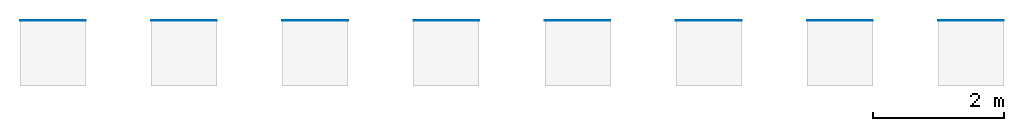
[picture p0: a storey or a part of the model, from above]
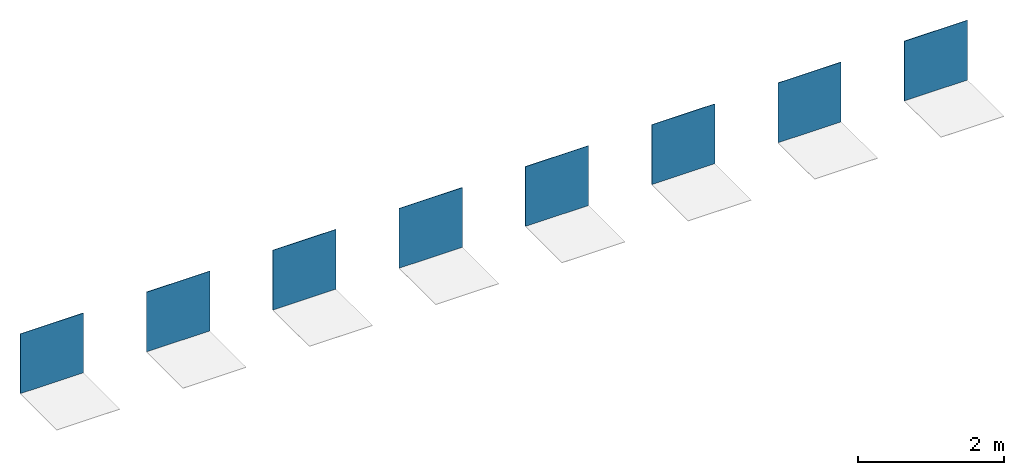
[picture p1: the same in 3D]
Properties of the parts of a building model (IFC2X3), part 1 of 2

# File
Description: ViewDefinition [CoordinationView_V2.0]
Time: 2025-06-20T12:25:39
Written by: The EXPRESS Data Manager Version 5.02.0100.07 : 28 Aug 2013
Made in: 21.1.90.15 - Exporter 21.1.90.15 - Alternate UI 21.1.90.15
Comment: STEP Physical File produced by: The EXPRESS Data Manager Version 5.02.0100.07 : 28 Aug 2013 * Module: EDMstepFileFactory/EDMstandAlone * Creation date: Fri Jun 20 12:25:39 2025 * Host: STB002 * Database: C:\Users\LARISS~1\AppData\Local\Temp\234e31d9-e186-458c-9206-d387dea7a233\4657faa5-0b9c-4604-aaa0-1ea8c5e9b940\ifc * Database version: 5507 * Database creation date: Fri Jun 20 12:25:38 2025 * Schema: IFC2X3 * Model: DataRepository.ifc * Model creation date: Fri Jun 20 12:25:39 2025 * Header model: DataRepository.ifc_HeaderModel * Header model creation date: Fri Jun 20 12:25:39 2025 * EDMuser: sdai-user * EDMgroup: sdai-group * License ID and type: 5605 : Permanent license. Expiry date: * EDMstepFileFactory options: 020000

# IfcSite, Default
RefLatitude: 42, 24, 53, 508911; RefLongitude: -71, -15, -29, -58837; RefElevation: 0 mm
Pset_ProductRequirements - Category: Project Information

# IfcBuilding
Pset_BuildingCommon - NumberOfStoreys: 1
Pset_ProductRequirements - Category: Project Information

# IfcBuildingStorey: Level:Level 1, Level 1
LongName: Level 1; Elevation: 0 mm
Pset_AirSideSystemInformation - Name: Level 1
Pset_ProductRequirements - Name: Level 1; Category: Levels

# IfcCovering: Floor:REVIGRÉS-LOCUS-HEXAGONO-16,5X19-SILK-ALLOY, Floor:REVIGRÉS-LOCUS-HEXAGONO-16,5X19-SILK-ALLOY:36414
In: Level 1
Type - PredefinedType: CLADDING; Material: REVIGRÉS-LOCUS-HEXAGONO-16,5x19-SILK-ALLOY 8.5 mm
Type - Pset_CoveringCommon - Reference: 332GV3V791; Material: Grés porcelânico
Type - Pset_ElementShading - Roughness: 304.8 mm
Type - Pset_ManufacturerTypeInformation - Manufacturer: REVIGRÉS
Type - Pset_ProductRequirements - Category: Floors
Type - Pset_QuantityTakeOff - Reference: 332GV3V791
Type - IFC.REVIGRÉS-Dados do fabricante-Floor Covering - FabricanteURL: https://www.revigres.pt/; ReferenciaModelo: Locus; NumeroGlobalDeItemComercial: 332GV3V761; Acabamento: SILK; Material: Grés porcelânico; IdentificadorDoOperadorEconomico: 501840856; UrlFabricanteArtigo: https://www.revigres.pt/colecoes/locus; PaisOrigem: Portugal
Type - IFC.REVIGRÉS-Dados de desempenho-Floor Covering - Rectilinearidade: ± 0.2% máx.± 0.8 mm; Ortogonalidade: ± 0.2% máx.± 1.5 mm; PlanaridadeDaSuperficie: ± 0.3% máx. ± 1.8 mm; QualidadeDaSuperficie: Cumpre; AbsorcaoDeAgua: < 0.05%; ModuloDeRuptura: > 45 N/mm²; ResistenciaAFlexao: > 2000 N; ResistenciaAAbrasaoProfunda: < 120 mm³; DilatacaoTermicaLinear: ≤ 8,0x10-6 °C-1; ResistenciaAoChoqueTermico: Resiste; DurabilidadeInterior: Cumpre; DurabilidadeResistenciaAoGeloDegelo: Resiste; ResistenciaAoEscorregamentoDIN51130: R9; ResistenciaAoEscorregamentoDIN51097: A; ResistenciaAoEscorregamentoENV51097: A; ResistenciaAoEscorregamentoENV12633: Class 1; ResistenciaAoEscorregamentoBS7976: -; ResistenciaAoEscorregamentoANSIA1371: ≥0,42; ResistenciaAoDeslizamentoENV12633: Class 1; ResistenciaAoDeslizamentoBS7976: -; ResistenciaAsManchas: Class 5; LibertacaoDeCadmio: 0; LibertacaoDeChumbo: 0
Type - IFC.REVIGRÉS-Dados de especificação-Floor Covering - VariacaoTonalidade: 3; NivelDeTrafego: 5; EPavimento: Sim; ERevestimento: Sim; EExterno: Sim
Type - IFC.REVIGRÉS-Dados geométricos-Floor Covering - AlturaNominal: 8.5 mm; ComprimentoNominal: 16.5 mm; LarguraNominal: 19 mm
Type - IFC.REVIGRÉS-Dados de sustentabilidade-Floor Covering - ItemEParcialmenteReciclado: 0; EnergiaTermicaExportada: 0; ItemENovo: Sim; ItemEReciclado: Não; VidaÚtilEsperada: 50; SubstanciasPerigosas: Não; PotencialDeEsgotamentoAbioticoDosRecursosNaoFosseisMineraisEMetais: 0.000701; PotencialDeAquecimentoGlobalBiogenico: -0.48; CombustiveisFosseisComPotencialDeAquecimentoGlobal: 13.9; PotencialDeAquecimentoGlobalUsoDoSoloEMudancaDeUsoDoSolo: 0.0246; PotencialDeEutrofizacaoFraccaoDeNutrientesQueAtingemOCompartimentoFinalDeAguaDoce: 0.000189; PotencialDeEutrofizacaoFraccaoDeNutrientesQueAtingemOCompartimentoFinalMarinho: 0.0122; EnergiaRecuperada: 0.00739; ConsumoDeAguaDoce: 0.113; UtilizacaoLiquidaDeAguaDoce: 0.113; ResiduosPerigososEliminados: 0.00221; ResiduosNaoPerigososEliminados: 1.83; MassaTotalDeResiduosRadioactivosEliminados: 0.000394; EnergiaElectricaExportada: 1.55; MateriaisParaRecuperacaoDeEnergia: 0.00739; MateriaisParaReciclagem: 0.0253; UnidadeEPD: 1 m²
Type - IFC.REVIGRÉS-Dados gerais-Floor Covering - Nome: REVIGRÉS-LOCUS-HEXAGONO-16.5x19-SILK-ALLOY; TipoProduto: Prensado a seco: grupo BIa UGL | Grés porcelânico técnico; NumeroDeRegistoDAP: EPD-REV-20240006-CCC1-EN; ReferenciaDAP: -; URL: https://www.revigres.pt/colecoes/locus
Classification: C3010 (Uniformat)
Pset_CoveringCommon - TotalThickness: 8.5 mm
IFC.REVIGRÉS-Dados do fabricante-Floor Covering - Type: Floor: REVIGRÉS-LOCUS-HEXAGONO-16,5X19-SILK-ALLOY
IFC.REVIGRÉS-Dados de desempenho-Floor Covering - Type: Floor: REVIGRÉS-LOCUS-HEXAGONO-16,5X19-SILK-ALLOY
IFC.REVIGRÉS-Dados de especificação-Floor Covering - Type: Floor: REVIGRÉS-LOCUS-HEXAGONO-16,5X19-SILK-ALLOY
IFC.REVIGRÉS-Dados geométricos-Floor Covering - Type: Floor: REVIGRÉS-LOCUS-HEXAGONO-16,5X19-SILK-ALLOY
IFC.REVIGRÉS-Dados de sustentabilidade-Floor Covering - Type: Floor: REVIGRÉS-LOCUS-HEXAGONO-16,5X19-SILK-ALLOY

# IfcCovering: Floor:REVIGRÉS-LOCUS-HEXAGONO-16,5X19-SILK-BONE, Floor:REVIGRÉS-LOCUS-HEXAGONO-16,5X19-SILK-BONE:36732
In: Level 1
Type - PredefinedType: CLADDING; Material: REVIGRÉS-LOCUS-HEXAGONO-16,5x19-SILK-BONE 8.5 mm
Type - Pset_CoveringCommon - Reference: 332GV3V781; Material: Grés porcelânico
Type - Pset_ElementShading - Roughness: 304.8 mm
Type - Pset_ManufacturerTypeInformation - Manufacturer: REVIGRÉS
Type - Pset_ProductRequirements - Category: Floors
Type - Pset_QuantityTakeOff - Reference: 332GV3V781
Type - IFC.REVIGRÉS-Dados do fabricante-Floor Covering - FabricanteURL: https://www.revigres.pt/; ReferenciaModelo: Locus; NumeroGlobalDeItemComercial: 312GV3V771; Acabamento: SILK; Material: Grés porcelânico; IdentificadorDoOperadorEconomico: 501840856; UrlFabricanteArtigo: https://www.revigres.pt/colecoes/locus; PaisOrigem: Portugal
Type - IFC.REVIGRÉS-Dados de desempenho-Floor Covering - Rectilinearidade: ± 0.2% máx.± 0.8 mm; Ortogonalidade: ± 0.2% máx.± 1.5 mm; PlanaridadeDaSuperficie: ± 0.3% máx. ± 1.8 mm; QualidadeDaSuperficie: Cumpre; AbsorcaoDeAgua: < 0.05%; ModuloDeRuptura: > 45 N/mm²; ResistenciaAFlexao: > 2000 N; ResistenciaAAbrasaoProfunda: < 120 mm³; DilatacaoTermicaLinear: ≤ 8,0x10-6 °C-1; ResistenciaAoChoqueTermico: Resiste; DurabilidadeInterior: Cumpre; DurabilidadeResistenciaAoGeloDegelo: Resiste; ResistenciaAoEscorregamentoDIN51130: R9; ResistenciaAoEscorregamentoDIN51097: A; ResistenciaAoEscorregamentoENV51097: A; ResistenciaAoEscorregamentoENV12633: Class 1; ResistenciaAoEscorregamentoBS7976: -; ResistenciaAoEscorregamentoANSIA1371: ≥0,42; ResistenciaAoDeslizamentoENV12633: Class 1; ResistenciaAoDeslizamentoBS7976: -; ResistenciaAsManchas: Class 5; LibertacaoDeCadmio: 0; LibertacaoDeChumbo: 0
Type - IFC.REVIGRÉS-Dados de especificação-Floor Covering - VariacaoTonalidade: 3; NivelDeTrafego: 5; EPavimento: Sim; ERevestimento: Sim; EExterno: Sim
Type - IFC.REVIGRÉS-Dados geométricos-Floor Covering - AlturaNominal: 8.5 mm; ComprimentoNominal: 16.5 mm; LarguraNominal: 19 mm
Type - IFC.REVIGRÉS-Dados de sustentabilidade-Floor Covering - ItemEParcialmenteReciclado: 0; EnergiaTermicaExportada: 0; ItemENovo: Sim; ItemEReciclado: Não; VidaÚtilEsperada: 50; SubstanciasPerigosas: Não; PotencialDeEsgotamentoAbioticoDosRecursosNaoFosseisMineraisEMetais: 0.000701; PotencialDeAquecimentoGlobalBiogenico: -0.48; CombustiveisFosseisComPotencialDeAquecimentoGlobal: 13.9; PotencialDeAquecimentoGlobalUsoDoSoloEMudancaDeUsoDoSolo: 0.0246; PotencialDeEutrofizacaoFraccaoDeNutrientesQueAtingemOCompartimentoFinalDeAguaDoce: 0.000189; PotencialDeEutrofizacaoFraccaoDeNutrientesQueAtingemOCompartimentoFinalMarinho: 0.0122; EnergiaRecuperada: 0.00739; ConsumoDeAguaDoce: 0.113; UtilizacaoLiquidaDeAguaDoce: 0.113; ResiduosPerigososEliminados: 0.00221; ResiduosNaoPerigososEliminados: 1.83; MassaTotalDeResiduosRadioactivosEliminados: 0.000394; EnergiaElectricaExportada: 1.55; MateriaisParaRecuperacaoDeEnergia: 0.00739; MateriaisParaReciclagem: 0.0253; UnidadeEPD: 1 m²
Type - IFC.REVIGRÉS-Dados gerais-Floor Covering - Nome: REVIGRÉS-LOCUS-HEXAGONO-16.5x19-SILK-BONE; TipoProduto: Prensado a seco: grupo BIa UGL | Grés porcelânico técnico; NumeroDeRegistoDAP: EPD-REV-20240006-CCC1-EN; ReferenciaDAP: -; URL: https://www.revigres.pt/colecoes/locus
Classification: C3010 (Uniformat)
Pset_CoveringCommon - TotalThickness: 8.5 mm
IFC.REVIGRÉS-Dados do fabricante-Floor Covering - Type: Floor: REVIGRÉS-LOCUS-HEXAGONO-16,5X19-SILK-BONE
IFC.REVIGRÉS-Dados de desempenho-Floor Covering - Type: Floor: REVIGRÉS-LOCUS-HEXAGONO-16,5X19-SILK-BONE
IFC.REVIGRÉS-Dados de especificação-Floor Covering - Type: Floor: REVIGRÉS-LOCUS-HEXAGONO-16,5X19-SILK-BONE
IFC.REVIGRÉS-Dados geométricos-Floor Covering - Type: Floor: REVIGRÉS-LOCUS-HEXAGONO-16,5X19-SILK-BONE
IFC.REVIGRÉS-Dados de sustentabilidade-Floor Covering - Type: Floor: REVIGRÉS-LOCUS-HEXAGONO-16,5X19-SILK-BONE

# IfcCovering: Floor:REVIGRÉS-LOCUS-HEXAGONO-16,5X19-SILK-GRIS, Floor:REVIGRÉS-LOCUS-HEXAGONO-16,5X19-SILK-GRIS:37396
In: Level 1
Type - PredefinedType: CLADDING; Material: REVIGRÉS-LOCUS-HEXAGONO-16,5x19-SILK-GRIS 8.5 mm
Type - Pset_CoveringCommon - Reference: 312GV3V771; Material: Grés porcelânico
Type - Pset_ElementShading - Roughness: 304.8 mm
Type - Pset_ManufacturerTypeInformation - Manufacturer: REVIGRÉS
Type - Pset_ProductRequirements - Category: Floors
Type - Pset_QuantityTakeOff - Reference: 312GV3V771
Type - IFC.REVIGRÉS-Dados do fabricante-Floor Covering - FabricanteURL: https://www.revigres.pt/; ReferenciaModelo: Locus; NumeroGlobalDeItemComercial: 332GV3V781; Acabamento: SILK; Material: Grés porcelânico; IdentificadorDoOperadorEconomico: 501840856; UrlFabricanteArtigo: https://www.revigres.pt/colecoes/locus; PaisOrigem: Portugal
Type - IFC.REVIGRÉS-Dados de desempenho-Floor Covering - Rectilinearidade: ± 0.2% máx.± 0.8 mm; Ortogonalidade: ± 0.2% máx.± 1.5 mm; PlanaridadeDaSuperficie: ± 0.3% máx. ± 1.8 mm; QualidadeDaSuperficie: Cumpre; AbsorcaoDeAgua: < 0.05%; ModuloDeRuptura: > 45 N/mm²; ResistenciaAFlexao: > 2000 N; ResistenciaAAbrasaoProfunda: < 120 mm³; DilatacaoTermicaLinear: ≤ 8,0x10-6 °C-1; ResistenciaAoChoqueTermico: Resiste; DurabilidadeInterior: Cumpre; DurabilidadeResistenciaAoGeloDegelo: Resiste; ResistenciaAoEscorregamentoDIN51130: R9; ResistenciaAoEscorregamentoDIN51097: A; ResistenciaAoEscorregamentoENV51097: A; ResistenciaAoEscorregamentoENV12633: Class 1; ResistenciaAoEscorregamentoBS7976: -; ResistenciaAoEscorregamentoANSIA1371: ≥0,42; ResistenciaAoDeslizamentoENV12633: Class 1; ResistenciaAoDeslizamentoBS7976: -; ResistenciaAsManchas: Class 5; LibertacaoDeCadmio: 0; LibertacaoDeChumbo: 0
Type - IFC.REVIGRÉS-Dados de especificação-Floor Covering - VariacaoTonalidade: 3; NivelDeTrafego: 5; EPavimento: Sim; ERevestimento: Sim; EExterno: Sim
Type - IFC.REVIGRÉS-Dados geométricos-Floor Covering - AlturaNominal: 8.5 mm; ComprimentoNominal: 16.5 mm; LarguraNominal: 19 mm
Type - IFC.REVIGRÉS-Dados de sustentabilidade-Floor Covering - EnergiaTermicaExportada: 0; ItemENovo: Sim; ItemEParcialmenteReciclado: 0.23; ItemEReciclado: Sim; VidaÚtilEsperada: 50; SubstanciasPerigosas: Não; PotencialDeEsgotamentoAbioticoDosRecursosNaoFosseisMineraisEMetais: 0.000701; PotencialDeAquecimentoGlobalBiogenico: -0.48; CombustiveisFosseisComPotencialDeAquecimentoGlobal: 13.9; PotencialDeAquecimentoGlobalUsoDoSoloEMudancaDeUsoDoSolo: 0.0246; PotencialDeEutrofizacaoFraccaoDeNutrientesQueAtingemOCompartimentoFinalDeAguaDoce: 0.000189; PotencialDeEutrofizacaoFraccaoDeNutrientesQueAtingemOCompartimentoFinalMarinho: 0.0122; EnergiaRecuperada: 0.00739; ConsumoDeAguaDoce: 0.113; UtilizacaoLiquidaDeAguaDoce: 0.113; ResiduosPerigososEliminados: 0.00221; ResiduosNaoPerigososEliminados: 1.83; MassaTotalDeResiduosRadioactivosEliminados: 0.000394; EnergiaElectricaExportada: 1.55; MateriaisParaRecuperacaoDeEnergia: 0.00739; MateriaisParaReciclagem: 0.0253; UnidadeEPD: 1 m²
Type - IFC.REVIGRÉS-Dados gerais-Floor Covering - Nome: REVIGRÉS-LOCUS-HEXAGONO-16.5x19-SILK-GRIS; TipoProduto: Prensado a seco: grupo BIa UGL | Grés porcelânico técnico; NumeroDeRegistoDAP: EPD-REV-20240006-CCC1-EN; ReferenciaDAP: -; URL: https://www.revigres.pt/colecoes/locus
Classification: C3010 (Uniformat)
Pset_CoveringCommon - TotalThickness: 8.5 mm
IFC.REVIGRÉS-Dados do fabricante-Floor Covering - Type: Floor: REVIGRÉS-LOCUS-HEXAGONO-16,5X19-SILK-GRIS
IFC.REVIGRÉS-Dados de desempenho-Floor Covering - Type: Floor: REVIGRÉS-LOCUS-HEXAGONO-16,5X19-SILK-GRIS
IFC.REVIGRÉS-Dados de especificação-Floor Covering - Type: Floor: REVIGRÉS-LOCUS-HEXAGONO-16,5X19-SILK-GRIS
IFC.REVIGRÉS-Dados geométricos-Floor Covering - Type: Floor: REVIGRÉS-LOCUS-HEXAGONO-16,5X19-SILK-GRIS
IFC.REVIGRÉS-Dados de sustentabilidade-Floor Covering - Type: Floor: REVIGRÉS-LOCUS-HEXAGONO-16,5X19-SILK-GRIS

# IfcCovering: Floor:REVIGRÉS-LOCUS-HEXAGONO-16,5X19-SILK-SMOG, Floor:REVIGRÉS-LOCUS-HEXAGONO-16,5X19-SILK-SMOG:37911
In: Level 1
Type - PredefinedType: CLADDING; Material: REVIGRÉS-LOCUS-HEXAGONO-16,5x19-SILK-SMOG 8.5 mm
Type - Pset_CoveringCommon - Reference: 332GV3V761; Material: Grés porcelânico
Type - Pset_ElementShading - Roughness: 304.8 mm
Type - Pset_ManufacturerTypeInformation - Manufacturer: REVIGRÉS
Type - Pset_ProductRequirements - Category: Floors
Type - Pset_QuantityTakeOff - Reference: 332GV3V761
Type - IFC.REVIGRÉS-Dados do fabricante-Floor Covering - FabricanteURL: https://www.revigres.pt/; ReferenciaModelo: Locus; NumeroGlobalDeItemComercial: 332GV3V791; Acabamento: SILK; Material: Grés porcelânico; IdentificadorDoOperadorEconomico: 501840856; UrlFabricanteArtigo: https://www.revigres.pt/colecoes/locus; PaisOrigem: Portugal
Type - IFC.REVIGRÉS-Dados de desempenho-Floor Covering - Rectilinearidade: ± 0.2% máx.± 0.8 mm; Ortogonalidade: ± 0.2% máx.± 1.5 mm; PlanaridadeDaSuperficie: ± 0.3% máx. ± 1.8 mm; QualidadeDaSuperficie: Cumpre; AbsorcaoDeAgua: < 0.05%; ModuloDeRuptura: > 45 N/mm²; ResistenciaAFlexao: > 2000 N; ResistenciaAAbrasaoProfunda: < 120 mm³; DilatacaoTermicaLinear: ≤ 8,0x10-6 °C-1; ResistenciaAoChoqueTermico: Resiste; DurabilidadeInterior: Cumpre; DurabilidadeResistenciaAoGeloDegelo: Resiste; ResistenciaAoEscorregamentoDIN51130: R9; ResistenciaAoEscorregamentoDIN51097: A; ResistenciaAoEscorregamentoENV51097: A; ResistenciaAoEscorregamentoENV12633: Class 1; ResistenciaAoEscorregamentoBS7976: -; ResistenciaAoEscorregamentoANSIA1371: ≥0,42; ResistenciaAoDeslizamentoENV12633: Class 1; ResistenciaAoDeslizamentoBS7976: -; ResistenciaAsManchas: Class 5; LibertacaoDeCadmio: 0; LibertacaoDeChumbo: 0
Type - IFC.REVIGRÉS-Dados de especificação-Floor Covering - VariacaoTonalidade: 3; NivelDeTrafego: 5; EPavimento: Sim; ERevestimento: Sim; EExterno: Sim
Type - IFC.REVIGRÉS-Dados geométricos-Floor Covering - AlturaNominal: 8.5 mm; ComprimentoNominal: 16.5 mm; LarguraNominal: 19 mm
Type - IFC.REVIGRÉS-Dados de sustentabilidade-Floor Covering - EnergiaTermicaExportada: 0; ItemENovo: Sim; ItemEParcialmenteReciclado: 0.29; ItemEReciclado: Sim; VidaÚtilEsperada: 50; SubstanciasPerigosas: Não; PotencialDeEsgotamentoAbioticoDosRecursosNaoFosseisMineraisEMetais: 0.000701; PotencialDeAquecimentoGlobalBiogenico: -0.48; CombustiveisFosseisComPotencialDeAquecimentoGlobal: 13.9; PotencialDeAquecimentoGlobalUsoDoSoloEMudancaDeUsoDoSolo: 0.0246; PotencialDeEutrofizacaoFraccaoDeNutrientesQueAtingemOCompartimentoFinalDeAguaDoce: 0.000189; PotencialDeEutrofizacaoFraccaoDeNutrientesQueAtingemOCompartimentoFinalMarinho: 0.0122; EnergiaRecuperada: 0.00739; ConsumoDeAguaDoce: 0.113; UtilizacaoLiquidaDeAguaDoce: 0.113; ResiduosPerigososEliminados: 0.00221; ResiduosNaoPerigososEliminados: 1.83; MassaTotalDeResiduosRadioactivosEliminados: 0.000394; EnergiaElectricaExportada: 1.55; MateriaisParaRecuperacaoDeEnergia: 0.00739; MateriaisParaReciclagem: 0.0253; UnidadeEPD: 1 m²
Type - IFC.REVIGRÉS-Dados gerais-Floor Covering - Nome: REVIGRÉS-LOCUS-HEXAGONO-16.5x19-SILK-SMOG; TipoProduto: Prensado a seco: grupo BIa UGL | Grés porcelânico técnico; NumeroDeRegistoDAP: EPD-REV-20240006-CCC1-EN; ReferenciaDAP: -; URL: https://www.revigres.pt/colecoes/locus
Classification: C3010 (Uniformat)
Pset_CoveringCommon - TotalThickness: 8.5 mm
IFC.REVIGRÉS-Dados do fabricante-Floor Covering - Type: Floor: REVIGRÉS-LOCUS-HEXAGONO-16,5X19-SILK-SMOG
IFC.REVIGRÉS-Dados de desempenho-Floor Covering - Type: Floor: REVIGRÉS-LOCUS-HEXAGONO-16,5X19-SILK-SMOG
IFC.REVIGRÉS-Dados de especificação-Floor Covering - Type: Floor: REVIGRÉS-LOCUS-HEXAGONO-16,5X19-SILK-SMOG
IFC.REVIGRÉS-Dados geométricos-Floor Covering - Type: Floor: REVIGRÉS-LOCUS-HEXAGONO-16,5X19-SILK-SMOG
IFC.REVIGRÉS-Dados de sustentabilidade-Floor Covering - Type: Floor: REVIGRÉS-LOCUS-HEXAGONO-16,5X19-SILK-SMOG

# IfcCovering: Floor:REVIGRÉS-LOCUS-HEXAGONO-16,5X19-SOFT GRIP-ALLOY, Floor:REVIGRÉS-LOCUS-HEXAGONO-16,5X19-SOFT GRIP-ALLOY:112818
In: Level 1
Type - PredefinedType: CLADDING; Material: REVIGRÉS-LOCUS-HEXAGONO-16,5x19-SILK-ALLOY 8.5 mm
Type - Pset_CoveringCommon - Reference: 332FV3V761; Material: Grés porcelânico
Type - Pset_ElementShading - Roughness: 304.8 mm
Type - Pset_ManufacturerTypeInformation - Manufacturer: REVIGRÉS
Type - Pset_ProductRequirements - Category: Floors
Type - Pset_QuantityTakeOff - Reference: 332FV3V761
Type - IFC.REVIGRÉS-Dados do fabricante-Floor Covering - FabricanteURL: https://www.revigres.pt/; ReferenciaModelo: Locus; NumeroGlobalDeItemComercial: 332FV3V761; Acabamento: SOFT; Material: Grés porcelânico; IdentificadorDoOperadorEconomico: 501840856; UrlFabricanteArtigo: https://www.revigres.pt/colecoes/locus; PaisOrigem: Portugal
Type - IFC.REVIGRÉS-Dados de desempenho-Floor Covering - Rectilinearidade: ± 0.2% máx ± 1.0 mm; Ortogonalidade: ± 0.2% máx.± 1.5 mm; PlanaridadeDaSuperficie: ± 0.3% máx. ± 1.8 mm; QualidadeDaSuperficie: Cumpre; AbsorcaoDeAgua: < 0.05%; ModuloDeRuptura: > 45 N/mm²; ResistenciaAFlexao: > 2000 N; ResistenciaAAbrasaoProfunda: < 120 mm³; DilatacaoTermicaLinear: ≤ 8,0x10-6 °C-1; ResistenciaAoChoqueTermico: Resiste; DurabilidadeInterior: Cumpre; DurabilidadeResistenciaAoGeloDegelo: Resiste; ResistenciaAoEscorregamentoDIN51130: R11; ResistenciaAoEscorregamentoDIN51097: A; ResistenciaAoEscorregamentoENV51097: A; ResistenciaAoEscorregamentoENV12633: Class 2; ResistenciaAoEscorregamentoBS7976: > 36; ResistenciaAoEscorregamentoANSIA1371: ≥0,42; ResistenciaAoDeslizamentoENV12633: Class 2; ResistenciaAoDeslizamentoBS7976: > 36; ResistenciaAsManchas: Class 5; LibertacaoDeCadmio: 0; LibertacaoDeChumbo: 0
Type - IFC.REVIGRÉS-Dados de especificação-Floor Covering - VariacaoTonalidade: 3; NivelDeTrafego: 5; EPavimento: Sim; ERevestimento: Sim; EExterno: Sim
Type - IFC.REVIGRÉS-Dados geométricos-Floor Covering - AlturaNominal: 8.5 mm; ComprimentoNominal: 16.5 mm; LarguraNominal: 19 mm
Type - IFC.REVIGRÉS-Dados de sustentabilidade-Floor Covering - ItemEParcialmenteReciclado: 0; EnergiaTermicaExportada: 0; ItemENovo: Sim; ItemEReciclado: Não; VidaÚtilEsperada: 50; SubstanciasPerigosas: Não; PotencialDeEsgotamentoAbioticoDosRecursosNaoFosseisMineraisEMetais: 0.000701; PotencialDeAquecimentoGlobalBiogenico: -0.48; CombustiveisFosseisComPotencialDeAquecimentoGlobal: 13.9; PotencialDeAquecimentoGlobalUsoDoSoloEMudancaDeUsoDoSolo: 0.0246; PotencialDeEutrofizacaoFraccaoDeNutrientesQueAtingemOCompartimentoFinalDeAguaDoce: 0.000189; PotencialDeEutrofizacaoFraccaoDeNutrientesQueAtingemOCompartimentoFinalMarinho: 0.0122; EnergiaRecuperada: 0.00739; ConsumoDeAguaDoce: 0.113; UtilizacaoLiquidaDeAguaDoce: 0.113; ResiduosPerigososEliminados: 0.00221; ResiduosNaoPerigososEliminados: 1.83; MassaTotalDeResiduosRadioactivosEliminados: 0.000394; EnergiaElectricaExportada: 1.55; MateriaisParaRecuperacaoDeEnergia: 0.00739; MateriaisParaReciclagem: 0.0253; UnidadeEPD: 1 m²
Type - IFC.REVIGRÉS-Dados gerais-Floor Covering - Nome: REVIGRÉS-LOCUS-HEXAGONO-16.5x19-SOFT GRIP-ALLOY; TipoProduto: Prensado a seco: grupo BIa UGL | Grés porcelânico técnico; NumeroDeRegistoDAP: EPD-REV-20240006-CCC1-EN; ReferenciaDAP: -; URL: https://www.revigres.pt/colecoes/locus
Classification: C3010 (Uniformat)
Pset_CoveringCommon - TotalThickness: 8.5 mm
IFC.REVIGRÉS-Dados do fabricante-Floor Covering - Type: Floor: REVIGRÉS-LOCUS-HEXAGONO-16,5X19-SOFT GRIP-ALLOY
IFC.REVIGRÉS-Dados de desempenho-Floor Covering - Type: Floor: REVIGRÉS-LOCUS-HEXAGONO-16,5X19-SOFT GRIP-ALLOY
IFC.REVIGRÉS-Dados de especificação-Floor Covering - Type: Floor: REVIGRÉS-LOCUS-HEXAGONO-16,5X19-SOFT GRIP-ALLOY
IFC.REVIGRÉS-Dados geométricos-Floor Covering - Type: Floor: REVIGRÉS-LOCUS-HEXAGONO-16,5X19-SOFT GRIP-ALLOY
IFC.REVIGRÉS-Dados de sustentabilidade-Floor Covering - Type: Floor: REVIGRÉS-LOCUS-HEXAGONO-16,5X19-SOFT GRIP-ALLOY

# IfcCovering: Floor:REVIGRÉS-LOCUS-HEXAGONO-16,5X19-SOFT GRIP-BONE, Floor:REVIGRÉS-LOCUS-HEXAGONO-16,5X19-SOFT GRIP-BONE:112826
In: Level 1
Type - PredefinedType: CLADDING; Material: REVIGRÉS-LOCUS-HEXAGONO-16,5x19-SILK-BONE 8.5 mm
Type - Pset_CoveringCommon - Reference: 332FV3V771; Material: Grés porcelânico
Type - Pset_ElementShading - Roughness: 304.8 mm
Type - Pset_ManufacturerTypeInformation - Manufacturer: REVIGRÉS
Type - Pset_ProductRequirements - Category: Floors
Type - Pset_QuantityTakeOff - Reference: 332FV3V771
Type - IFC.REVIGRÉS-Dados do fabricante-Floor Covering - FabricanteURL: https://www.revigres.pt/; ReferenciaModelo: Locus; NumeroGlobalDeItemComercial: 332FV3V771; Acabamento: SOFT; Material: Grés porcelânico; IdentificadorDoOperadorEconomico: 501840856; UrlFabricanteArtigo: https://www.revigres.pt/colecoes/locus; PaisOrigem: Portugal
Type - IFC.REVIGRÉS-Dados de desempenho-Floor Covering - Rectilinearidade: ± 0.2% máx ± 1.0 mm; Ortogonalidade: ± 0.2% máx.± 1.5 mm; PlanaridadeDaSuperficie: ± 0.3% máx. ± 1.8 mm; QualidadeDaSuperficie: Cumpre; AbsorcaoDeAgua: < 0.05%; ModuloDeRuptura: > 45 N/mm²; ResistenciaAFlexao: > 2000 N; ResistenciaAAbrasaoProfunda: < 120 mm³; DilatacaoTermicaLinear: ≤ 8,0x10-6 °C-1; ResistenciaAoChoqueTermico: Resiste; DurabilidadeInterior: Cumpre; DurabilidadeResistenciaAoGeloDegelo: Resiste; ResistenciaAoEscorregamentoDIN51130: R11; ResistenciaAoEscorregamentoDIN51097: A; ResistenciaAoEscorregamentoENV51097: A; ResistenciaAoEscorregamentoENV12633: Class 2; ResistenciaAoEscorregamentoBS7976: > 36; ResistenciaAoEscorregamentoANSIA1371: ≥0,42; ResistenciaAoDeslizamentoENV12633: Class 2; ResistenciaAoDeslizamentoBS7976: > 36; ResistenciaAsManchas: Class 5; LibertacaoDeCadmio: 0; LibertacaoDeChumbo: 0
Type - IFC.REVIGRÉS-Dados de especificação-Floor Covering - VariacaoTonalidade: 3; NivelDeTrafego: 5; EPavimento: Sim; ERevestimento: Sim; EExterno: Sim
Type - IFC.REVIGRÉS-Dados geométricos-Floor Covering - AlturaNominal: 8.5 mm; ComprimentoNominal: 16.5 mm; LarguraNominal: 19 mm
Type - IFC.REVIGRÉS-Dados de sustentabilidade-Floor Covering - ItemEParcialmenteReciclado: 0; EnergiaTermicaExportada: 0; ItemENovo: Sim; ItemEReciclado: Não; VidaÚtilEsperada: 50; SubstanciasPerigosas: Não; PotencialDeEsgotamentoAbioticoDosRecursosNaoFosseisMineraisEMetais: 0.000701; PotencialDeAquecimentoGlobalBiogenico: -0.48; CombustiveisFosseisComPotencialDeAquecimentoGlobal: 13.9; PotencialDeAquecimentoGlobalUsoDoSoloEMudancaDeUsoDoSolo: 0.0246; PotencialDeEutrofizacaoFraccaoDeNutrientesQueAtingemOCompartimentoFinalDeAguaDoce: 0.000189; PotencialDeEutrofizacaoFraccaoDeNutrientesQueAtingemOCompartimentoFinalMarinho: 0.0122; EnergiaRecuperada: 0.00739; ConsumoDeAguaDoce: 0.113; UtilizacaoLiquidaDeAguaDoce: 0.113; ResiduosPerigososEliminados: 0.00221; ResiduosNaoPerigososEliminados: 1.83; MassaTotalDeResiduosRadioactivosEliminados: 0.000394; EnergiaElectricaExportada: 1.55; MateriaisParaRecuperacaoDeEnergia: 0.00739; MateriaisParaReciclagem: 0.0253; UnidadeEPD: 1 m²
Type - IFC.REVIGRÉS-Dados gerais-Floor Covering - Nome: REVIGRÉS-LOCUS-HEXAGONO-16.5x19-SOFT GRIP-BONE; TipoProduto: Prensado a seco: grupo BIa UGL | Grés porcelânico técnico; NumeroDeRegistoDAP: EPD-REV-20240006-CCC1-EN; ReferenciaDAP: -; URL: https://www.revigres.pt/colecoes/locus
Classification: C3010 (Uniformat)
Pset_CoveringCommon - TotalThickness: 8.5 mm
IFC.REVIGRÉS-Dados do fabricante-Floor Covering - Type: Floor: REVIGRÉS-LOCUS-HEXAGONO-16,5X19-SOFT GRIP-BONE
IFC.REVIGRÉS-Dados de desempenho-Floor Covering - Type: Floor: REVIGRÉS-LOCUS-HEXAGONO-16,5X19-SOFT GRIP-BONE
IFC.REVIGRÉS-Dados de especificação-Floor Covering - Type: Floor: REVIGRÉS-LOCUS-HEXAGONO-16,5X19-SOFT GRIP-BONE
IFC.REVIGRÉS-Dados geométricos-Floor Covering - Type: Floor: REVIGRÉS-LOCUS-HEXAGONO-16,5X19-SOFT GRIP-BONE
IFC.REVIGRÉS-Dados de sustentabilidade-Floor Covering - Type: Floor: REVIGRÉS-LOCUS-HEXAGONO-16,5X19-SOFT GRIP-BONE

# IfcCovering: Floor:REVIGRÉS-LOCUS-HEXAGONO-16,5X19-SOFT GRIP-GRIS, Floor:REVIGRÉS-LOCUS-HEXAGONO-16,5X19-SOFT GRIP-GRIS:112834
In: Level 1
Type - PredefinedType: CLADDING; Material: REVIGRÉS-LOCUS-HEXAGONO-16,5x19-SILK-GRIS 8.5 mm
Type - Pset_CoveringCommon - Reference: 332FV3V781; Material: Grés porcelânico
Type - Pset_ElementShading - Roughness: 304.8 mm
Type - Pset_ManufacturerTypeInformation - Manufacturer: REVIGRÉS
Type - Pset_ProductRequirements - Category: Floors
Type - Pset_QuantityTakeOff - Reference: 332FV3V781
Type - IFC.REVIGRÉS-Dados do fabricante-Floor Covering - FabricanteURL: https://www.revigres.pt/; ReferenciaModelo: Locus; NumeroGlobalDeItemComercial: 332FV3V781; Acabamento: SOFT; Material: Grés porcelânico; IdentificadorDoOperadorEconomico: 501840856; UrlFabricanteArtigo: https://www.revigres.pt/colecoes/locus; PaisOrigem: Portugal
Type - IFC.REVIGRÉS-Dados de desempenho-Floor Covering - Rectilinearidade: ± 0.2% máx ± 1.0 mm; Ortogonalidade: ± 0.2% máx.± 1.5 mm; PlanaridadeDaSuperficie: ± 0.3% máx. ± 1.8 mm; QualidadeDaSuperficie: Cumpre; AbsorcaoDeAgua: < 0.05%; ModuloDeRuptura: > 45 N/mm²; ResistenciaAFlexao: > 2000 N; ResistenciaAAbrasaoProfunda: < 120 mm³; DilatacaoTermicaLinear: ≤ 8,0x10-6 °C-1; ResistenciaAoChoqueTermico: Resiste; DurabilidadeInterior: Cumpre; DurabilidadeResistenciaAoGeloDegelo: Resiste; ResistenciaAoEscorregamentoDIN51130: R11; ResistenciaAoEscorregamentoDIN51097: A; ResistenciaAoEscorregamentoENV51097: A; ResistenciaAoEscorregamentoENV12633: Class 2; ResistenciaAoEscorregamentoBS7976: > 36; ResistenciaAoEscorregamentoANSIA1371: ≥0,42; ResistenciaAoDeslizamentoENV12633: Class 2; ResistenciaAoDeslizamentoBS7976: > 36; ResistenciaAsManchas: Class 5; LibertacaoDeCadmio: 0; LibertacaoDeChumbo: 0
Type - IFC.REVIGRÉS-Dados de especificação-Floor Covering - VariacaoTonalidade: 3; NivelDeTrafego: 5; EPavimento: Sim; ERevestimento: Sim; EExterno: Sim
Type - IFC.REVIGRÉS-Dados geométricos-Floor Covering - AlturaNominal: 8.5 mm; ComprimentoNominal: 16.5 mm; LarguraNominal: 19 mm
Type - IFC.REVIGRÉS-Dados de sustentabilidade-Floor Covering - EnergiaTermicaExportada: 0; ItemENovo: Sim; ItemEParcialmenteReciclado: 0.23; ItemEReciclado: Sim; VidaÚtilEsperada: 50; SubstanciasPerigosas: Não; PotencialDeEsgotamentoAbioticoDosRecursosNaoFosseisMineraisEMetais: 0.000701; PotencialDeAquecimentoGlobalBiogenico: -0.48; CombustiveisFosseisComPotencialDeAquecimentoGlobal: 13.9; PotencialDeAquecimentoGlobalUsoDoSoloEMudancaDeUsoDoSolo: 0.0246; PotencialDeEutrofizacaoFraccaoDeNutrientesQueAtingemOCompartimentoFinalDeAguaDoce: 0.000189; PotencialDeEutrofizacaoFraccaoDeNutrientesQueAtingemOCompartimentoFinalMarinho: 0.0122; EnergiaRecuperada: 0.00739; ConsumoDeAguaDoce: 0.113; UtilizacaoLiquidaDeAguaDoce: 0.113; ResiduosPerigososEliminados: 0.00221; ResiduosNaoPerigososEliminados: 1.83; MassaTotalDeResiduosRadioactivosEliminados: 0.000394; EnergiaElectricaExportada: 1.55; MateriaisParaRecuperacaoDeEnergia: 0.00739; MateriaisParaReciclagem: 0.0253; UnidadeEPD: 1 m²
Type - IFC.REVIGRÉS-Dados gerais-Floor Covering - Nome: REVIGRÉS-LOCUS-HEXAGONO-16.5x19-SOFT GRIP-GRIS; TipoProduto: Prensado a seco: grupo BIa UGL | Grés porcelânico técnico; NumeroDeRegistoDAP: EPD-REV-20240006-CCC1-EN; ReferenciaDAP: -; URL: https://www.revigres.pt/colecoes/locus
Classification: C3010 (Uniformat)
Pset_CoveringCommon - TotalThickness: 8.5 mm
IFC.REVIGRÉS-Dados do fabricante-Floor Covering - Type: Floor: REVIGRÉS-LOCUS-HEXAGONO-16,5X19-SOFT GRIP-GRIS
IFC.REVIGRÉS-Dados de desempenho-Floor Covering - Type: Floor: REVIGRÉS-LOCUS-HEXAGONO-16,5X19-SOFT GRIP-GRIS
IFC.REVIGRÉS-Dados de especificação-Floor Covering - Type: Floor: REVIGRÉS-LOCUS-HEXAGONO-16,5X19-SOFT GRIP-GRIS
IFC.REVIGRÉS-Dados geométricos-Floor Covering - Type: Floor: REVIGRÉS-LOCUS-HEXAGONO-16,5X19-SOFT GRIP-GRIS
IFC.REVIGRÉS-Dados de sustentabilidade-Floor Covering - Type: Floor: REVIGRÉS-LOCUS-HEXAGONO-16,5X19-SOFT GRIP-GRIS

# IfcCovering: Floor:REVIGRÉS-LOCUS-HEXAGONO-16,5X19-SOFT GRIP-SMOG, Floor:REVIGRÉS-LOCUS-HEXAGONO-16,5X19-SOFT GRIP-SMOG:112842
In: Level 1
Type - PredefinedType: CLADDING; Material: REVIGRÉS-LOCUS-HEXAGONO-16,5x19-SILK-SMOG 8.5 mm
Type - Pset_CoveringCommon - Reference: 332FV3V791; Material: Grés porcelânico
Type - Pset_ElementShading - Roughness: 304.8 mm
Type - Pset_ManufacturerTypeInformation - Manufacturer: REVIGRÉS
Type - Pset_ProductRequirements - Category: Floors
Type - Pset_QuantityTakeOff - Reference: 332FV3V791
Type - IFC.REVIGRÉS-Dados do fabricante-Floor Covering - FabricanteURL: https://www.revigres.pt/; ReferenciaModelo: Locus; NumeroGlobalDeItemComercial: 332FV3V791; Acabamento: SOFT; Material: Grés porcelânico; IdentificadorDoOperadorEconomico: 501840856; UrlFabricanteArtigo: https://www.revigres.pt/colecoes/locus; PaisOrigem: Portugal
Type - IFC.REVIGRÉS-Dados de desempenho-Floor Covering - Rectilinearidade: ± 0.2% máx ± 1.0 mm; Ortogonalidade: ± 0.2% máx.± 1.5 mm; PlanaridadeDaSuperficie: ± 0.3% máx. ± 1.8 mm; QualidadeDaSuperficie: Cumpre; AbsorcaoDeAgua: < 0.05%; ModuloDeRuptura: > 45 N/mm²; ResistenciaAFlexao: > 2000 N; ResistenciaAAbrasaoProfunda: < 120 mm³; DilatacaoTermicaLinear: ≤ 8,0x10-6 °C-1; ResistenciaAoChoqueTermico: Resiste; DurabilidadeInterior: Cumpre; DurabilidadeResistenciaAoGeloDegelo: Resiste; ResistenciaAoEscorregamentoDIN51130: R11; ResistenciaAoEscorregamentoDIN51097: A; ResistenciaAoEscorregamentoENV51097: A; ResistenciaAoEscorregamentoENV12633: Class 2; ResistenciaAoEscorregamentoBS7976: > 36; ResistenciaAoEscorregamentoANSIA1371: ≥0,42; ResistenciaAoDeslizamentoENV12633: Class 2; ResistenciaAoDeslizamentoBS7976: > 36; ResistenciaAsManchas: Class 5; LibertacaoDeCadmio: 0; LibertacaoDeChumbo: 0
Type - IFC.REVIGRÉS-Dados de especificação-Floor Covering - VariacaoTonalidade: 3; NivelDeTrafego: 5; EPavimento: Sim; ERevestimento: Sim; EExterno: Sim
Type - IFC.REVIGRÉS-Dados geométricos-Floor Covering - AlturaNominal: 8.5 mm; ComprimentoNominal: 16.5 mm; LarguraNominal: 19 mm
Type - IFC.REVIGRÉS-Dados de sustentabilidade-Floor Covering - EnergiaTermicaExportada: 0; ItemENovo: Sim; ItemEParcialmenteReciclado: 0.29; ItemEReciclado: Sim; VidaÚtilEsperada: 50; SubstanciasPerigosas: Não; PotencialDeEsgotamentoAbioticoDosRecursosNaoFosseisMineraisEMetais: 0.000701; PotencialDeAquecimentoGlobalBiogenico: -0.48; CombustiveisFosseisComPotencialDeAquecimentoGlobal: 13.9; PotencialDeAquecimentoGlobalUsoDoSoloEMudancaDeUsoDoSolo: 0.0246; PotencialDeEutrofizacaoFraccaoDeNutrientesQueAtingemOCompartimentoFinalDeAguaDoce: 0.000189; PotencialDeEutrofizacaoFraccaoDeNutrientesQueAtingemOCompartimentoFinalMarinho: 0.0122; EnergiaRecuperada: 0.00739; ConsumoDeAguaDoce: 0.113; UtilizacaoLiquidaDeAguaDoce: 0.113; ResiduosPerigososEliminados: 0.00221; ResiduosNaoPerigososEliminados: 1.83; MassaTotalDeResiduosRadioactivosEliminados: 0.000394; EnergiaElectricaExportada: 1.55; MateriaisParaRecuperacaoDeEnergia: 0.00739; MateriaisParaReciclagem: 0.0253; UnidadeEPD: 1 m²
Type - IFC.REVIGRÉS-Dados gerais-Floor Covering - Nome: REVIGRÉS-LOCUS-HEXAGONO-16.5x19-SOFT GRIP-SMOG; TipoProduto: Prensado a seco: grupo BIa UGL | Grés porcelânico técnico; NumeroDeRegistoDAP: EPD-REV-20240006-CCC1-EN; ReferenciaDAP: -; URL: https://www.revigres.pt/colecoes/locus
Classification: C3010 (Uniformat)
Pset_CoveringCommon - TotalThickness: 8.5 mm
IFC.REVIGRÉS-Dados do fabricante-Floor Covering - Type: Floor: REVIGRÉS-LOCUS-HEXAGONO-16,5X19-SOFT GRIP-SMOG
IFC.REVIGRÉS-Dados de desempenho-Floor Covering - Type: Floor: REVIGRÉS-LOCUS-HEXAGONO-16,5X19-SOFT GRIP-SMOG
IFC.REVIGRÉS-Dados de especificação-Floor Covering - Type: Floor: REVIGRÉS-LOCUS-HEXAGONO-16,5X19-SOFT GRIP-SMOG
IFC.REVIGRÉS-Dados geométricos-Floor Covering - Type: Floor: REVIGRÉS-LOCUS-HEXAGONO-16,5X19-SOFT GRIP-SMOG
IFC.REVIGRÉS-Dados de sustentabilidade-Floor Covering - Type: Floor: REVIGRÉS-LOCUS-HEXAGONO-16,5X19-SOFT GRIP-SMOG

# IfcWallStandardCase: Basic Wall:REVIGRÉS-LOCUS-HEXAGONO-16,5X19-SILK-ALLOY, Basic Wall:REVIGRÉS-LOCUS-HEXAGONO-16,5X19-SILK-ALLOY:36403
In: Level 1
Type - PredefinedType: STANDARD; Material: REVIGRÉS-LOCUS-HEXAGONO-16,5x19-SILK-ALLOY 8.5 mm
Type - Pset_ElementShading - Roughness: 304.8 mm
Type - Pset_ManufacturerTypeInformation - Manufacturer: REVIGRÉS
Type - Pset_ProductRequirements - Category: Walls
Type - Pset_QuantityTakeOff - Reference: 332GV3V761
Type - Pset_ReinforcementBarPitchOfWall - Description: Stone effect in wall and floor full body porcelain tile; Reference: 332GV3V761
Type - Pset_WallCommon - Reference: 332GV3V761; IsExternal: no
Type - IFC.REVIGRÉS-Dados do fabricante-Wall Covering - FabricanteURL: https://www.revigres.pt/; ReferenciaModelo: Locus; NumeroGlobalDeItemComercial: 332GV3V761; Acabamento: SILK; Material: Grés porcelânico; IdentificadorDoOperadorEconomico: 501840856; UrlFabricanteArtigo: https://www.revigres.pt/colecoes/locus; PaisOrigem: Portugal
Type - IFC.REVIGRÉS-Dados de desempenho-Wall Covering - Rectilinearidade: ± 0.2% máx.± 0.8 mm; Ortogonalidade: ± 0.2% máx.± 1.5 mm; PlanaridadeDaSuperficie: ± 0.3% máx. ± 1.8 mm; QualidadeDaSuperficie: Cumpre; AbsorcaoDeAgua: < 0.05%; ModuloDeRuptura: > 45 N/mm²; ResistenciaAFlexao: > 2000 N; ResistenciaAAbrasaoProfunda: < 120 mm³; DilatacaoTermicaLinear: ≤ 8,0x10-6 °C-1; ResistenciaAoChoqueTermico: Resiste; DurabilidadeInterior: Cumpre; DurabilidadeResistenciaAoGeloDegelo: Resiste; ResistenciaAoEscorregamentoDIN51130: R9; ResistenciaAoEscorregamentoDIN51097: A; ResistenciaAoEscorregamentoENV51097: A; ResistenciaAoEscorregamentoENV12633: Class 1; ResistenciaAoEscorregamentoBS7976: -; ResistenciaAoEscorregamentoANSIA1371: ≥0,42; ResistenciaAoDeslizamentoENV12633: Class 1; ResistenciaAoDeslizamentoBS7976: -; ResistenciaAsManchas: Class 5; LibertacaoDeCadmio: 0; LibertacaoDeChumbo: 0
Type - IFC.REVIGRÉS-Dados de especificação-Wall Covering - VariacaoTonalidade: 3; NivelDeTrafego: 5; EPavimento: Sim; ERevestimento: Sim; EExterno: Sim
Type - IFC.REVIGRÉS-Dados geométricos-Wall Covering - AlturaNominal: 8.5 mm; ComprimentoNominal: 16.5 mm; LarguraNominal: 19 mm
Type - IFC.REVIGRÉS-Dados de sustentabilidade-Wall Covering - ItemENovo: Sim; ItemEParcialmenteReciclado: 0; ItemEReciclado: Não; VidaÚtilEsperada: 50; SubstanciasPerigosas: Não; PotencialDeEsgotamentoAbioticoDosRecursosNaoFosseisMineraisEMetais: 0.000701; PotencialDeAquecimentoGlobalBiogenico: -0.48; CombustiveisFosseisComPotencialDeAquecimentoGlobal: 13.9; PotencialDeAquecimentoGlobalUsoDoSoloEMudancaDeUsoDoSolo: 0.0246; PotencialDeEutrofizacaoFraccaoDeNutrientesQueAtingemOCompartimentoFinalDeAguaDoce: 0.000189; PotencialDeEutrofizacaoFraccaoDeNutrientesQueAtingemOCompartimentoFinalMarinho: 0.0122; PotencialPrivacaoDeAguaConsumoDeAguaPonderado: 4.5; EnergiaRecuperada: 0.00739; ConsumoDeAguaDoce: 0.113; UtilizacaoLiquidaDeAguaDoce: 0.113; ResiduosPerigososEliminados: 0.00221; ResiduosNaoPerigososEliminados: 1.83; MassaTotalDeResiduosRadioactivosEliminados: 0.000394; EnergiaElectricaExportada: 1.55; EnergiaTermicaExportada: 0; MateriaisParaRecuperacaoDeEnergia: 0.00739; MateriaisParaReciclagem: 0.0253; UnidadeEPD: 1 m²
Type - IFC.REVIGRÉS-Dados gerais-Wall Covering - Nome: REVIGRÉS-LOCUS-HEXAGONO-16.5x19-SILK-ALLOY; TipoProduto: Prensado a seco: grupo BIa UGL | Grés porcelânico técnico; NumeroDeRegistoDAP: EPD-REV-20240006-CCC1-EN; ReferenciaDAP: -; UrlDOP: -
Classification: C3010 (Uniformat)
Pset_WallCommon - ExtendToStructure: no; LoadBearing: no
IFC.REVIGRÉS-Dados do fabricante-Wall Covering - Type: Basic Wall: REVIGRÉS-LOCUS-HEXAGONO-16,5X19-SILK-ALLOY
IFC.REVIGRÉS-Dados de desempenho-Wall Covering - Type: Basic Wall: REVIGRÉS-LOCUS-HEXAGONO-16,5X19-SILK-ALLOY
IFC.REVIGRÉS-Dados de especificação-Wall Covering - Type: Basic Wall: REVIGRÉS-LOCUS-HEXAGONO-16,5X19-SILK-ALLOY
IFC.REVIGRÉS-Dados geométricos-Wall Covering - Type: Basic Wall: REVIGRÉS-LOCUS-HEXAGONO-16,5X19-SILK-ALLOY
IFC.REVIGRÉS-Dados de sustentabilidade-Wall Covering - Type: Basic Wall: REVIGRÉS-LOCUS-HEXAGONO-16,5X19-SILK-ALLOY

# IfcWallStandardCase: Basic Wall:REVIGRÉS-LOCUS-HEXAGONO-16,5X19-SILK-BONE, Basic Wall:REVIGRÉS-LOCUS-HEXAGONO-16,5X19-SILK-BONE:36721
In: Level 1
Type - PredefinedType: STANDARD; Material: REVIGRÉS-LOCUS-HEXAGONO-16,5x19-SILK-BONE 8.5 mm
Type - Pset_ElementShading - Roughness: 304.8 mm
Type - Pset_ManufacturerTypeInformation - Manufacturer: REVIGRÉS
Type - Pset_ProductRequirements - Category: Walls
Type - Pset_QuantityTakeOff - Reference: 312GV3V771
Type - Pset_ReinforcementBarPitchOfWall - Description: Stone effect in wall and floor full body porcelain tile; Reference: 312GV3V771
Type - Pset_WallCommon - IsExternal: no; Reference: 312GV3V771
Type - IFC.REVIGRÉS-Dados do fabricante-Wall Covering - FabricanteURL: https://www.revigres.pt/; ReferenciaModelo: Locus; NumeroGlobalDeItemComercial: 312GV3V771; Acabamento: SILK; Material: Grés porcelânico; IdentificadorDoOperadorEconomico: 501840856; UrlFabricanteArtigo: https://www.revigres.pt/colecoes/locus; PaisOrigem: Portugal
Type - IFC.REVIGRÉS-Dados de desempenho-Wall Covering - Rectilinearidade: ± 0.2% máx.± 0.8 mm; Ortogonalidade: ± 0.2% máx.± 1.5 mm; PlanaridadeDaSuperficie: ± 0.3% máx. ± 1.8 mm; QualidadeDaSuperficie: Cumpre; AbsorcaoDeAgua: < 0.05%; ModuloDeRuptura: > 45 N/mm²; ResistenciaAFlexao: > 2000 N; ResistenciaAAbrasaoProfunda: < 120 mm³; DilatacaoTermicaLinear: ≤ 8,0x10-6 °C-1; ResistenciaAoChoqueTermico: Resiste; DurabilidadeInterior: Cumpre; DurabilidadeResistenciaAoGeloDegelo: Resiste; ResistenciaAoEscorregamentoDIN51130: R9; ResistenciaAoEscorregamentoDIN51097: A; ResistenciaAoEscorregamentoENV51097: A; ResistenciaAoEscorregamentoENV12633: Class 1; ResistenciaAoEscorregamentoBS7976: -; ResistenciaAoEscorregamentoANSIA1371: ≥0,42; ResistenciaAoDeslizamentoENV12633: Class 1; ResistenciaAoDeslizamentoBS7976: -; ResistenciaAsManchas: Class 5; LibertacaoDeCadmio: 0; LibertacaoDeChumbo: 0
Type - IFC.REVIGRÉS-Dados de especificação-Wall Covering - VariacaoTonalidade: 3; NivelDeTrafego: 5; EPavimento: Sim; ERevestimento: Sim; EExterno: Sim
Type - IFC.REVIGRÉS-Dados geométricos-Wall Covering - AlturaNominal: 8.5 mm; ComprimentoNominal: 16.5 mm; LarguraNominal: 19 mm
Type - IFC.REVIGRÉS-Dados de sustentabilidade-Wall Covering - ItemEParcialmenteReciclado: 0; PotencialPrivacaoDeAguaConsumoDeAguaPonderado: 4.5; EnergiaTermicaExportada: 0; ItemENovo: Sim; ItemEReciclado: Não; VidaÚtilEsperada: 50; SubstanciasPerigosas: Não; PotencialDeEsgotamentoAbioticoDosRecursosNaoFosseisMineraisEMetais: 0.000701; PotencialDeAquecimentoGlobalBiogenico: -0.48; CombustiveisFosseisComPotencialDeAquecimentoGlobal: 13.9; PotencialDeAquecimentoGlobalUsoDoSoloEMudancaDeUsoDoSolo: 0.0246; PotencialDeEutrofizacaoFraccaoDeNutrientesQueAtingemOCompartimentoFinalDeAguaDoce: 0.000189; PotencialDeEutrofizacaoFraccaoDeNutrientesQueAtingemOCompartimentoFinalMarinho: 0.0122; EnergiaRecuperada: 0.00739; ConsumoDeAguaDoce: 0.113; UtilizacaoLiquidaDeAguaDoce: 0.113; ResiduosPerigososEliminados: 0.00221; ResiduosNaoPerigososEliminados: 1.83; MassaTotalDeResiduosRadioactivosEliminados: 0.000394; EnergiaElectricaExportada: 1.55; MateriaisParaRecuperacaoDeEnergia: 0.00739; MateriaisParaReciclagem: 0.0253; UnidadeEPD: 1 m²
Type - IFC.REVIGRÉS-Dados gerais-Wall Covering - Nome: REVIGRÉS-LOCUS-HEXAGONO-16.5x19-SILK-BONE; TipoProduto: Prensado a seco: grupo BIa UGL | Grés porcelânico técnico; NumeroDeRegistoDAP: EPD-REV-20240006-CCC1-EN; ReferenciaDAP: -; UrlDOP: -
Classification: C3010 (Uniformat)
Pset_WallCommon - ExtendToStructure: no; LoadBearing: no
IFC.REVIGRÉS-Dados do fabricante-Wall Covering - Type: Basic Wall: REVIGRÉS-LOCUS-HEXAGONO-16,5X19-SILK-BONE
IFC.REVIGRÉS-Dados de desempenho-Wall Covering - Type: Basic Wall: REVIGRÉS-LOCUS-HEXAGONO-16,5X19-SILK-BONE
IFC.REVIGRÉS-Dados de especificação-Wall Covering - Type: Basic Wall: REVIGRÉS-LOCUS-HEXAGONO-16,5X19-SILK-BONE
IFC.REVIGRÉS-Dados geométricos-Wall Covering - Type: Basic Wall: REVIGRÉS-LOCUS-HEXAGONO-16,5X19-SILK-BONE
IFC.REVIGRÉS-Dados de sustentabilidade-Wall Covering - Type: Basic Wall: REVIGRÉS-LOCUS-HEXAGONO-16,5X19-SILK-BONE

# IfcWallStandardCase: Basic Wall:REVIGRÉS-LOCUS-HEXAGONO-16,5X19-SILK-GRIS, Basic Wall:REVIGRÉS-LOCUS-HEXAGONO-16,5X19-SILK-GRIS:37385
In: Level 1
Type - PredefinedType: STANDARD; Material: REVIGRÉS-LOCUS-HEXAGONO-16,5x19-SILK-GRIS 8.5 mm
Type - Pset_ElementShading - Roughness: 304.8 mm
Type - Pset_ManufacturerTypeInformation - Manufacturer: REVIGRÉS
Type - Pset_ProductRequirements - Category: Walls
Type - Pset_QuantityTakeOff - Reference: 332GV3V781
Type - Pset_ReinforcementBarPitchOfWall - Description: Stone effect in wall and floor full body porcelain tile; Reference: 332GV3V781
Type - Pset_WallCommon - IsExternal: no; Reference: 332GV3V781
Type - IFC.REVIGRÉS-Dados do fabricante-Wall Covering - FabricanteURL: https://www.revigres.pt/; ReferenciaModelo: Locus; NumeroGlobalDeItemComercial: 332GV3V781; Acabamento: SILK; Material: Grés porcelânico; IdentificadorDoOperadorEconomico: 501840856; UrlFabricanteArtigo: https://www.revigres.pt/colecoes/locus; PaisOrigem: Portugal
Type - IFC.REVIGRÉS-Dados de desempenho-Wall Covering - Rectilinearidade: ± 0.2% máx.± 0.8 mm; Ortogonalidade: ± 0.2% máx.± 1.5 mm; PlanaridadeDaSuperficie: ± 0.3% máx. ± 1.8 mm; QualidadeDaSuperficie: Cumpre; AbsorcaoDeAgua: < 0.05%; ModuloDeRuptura: > 45 N/mm²; ResistenciaAFlexao: > 2000 N; ResistenciaAAbrasaoProfunda: < 120 mm³; DilatacaoTermicaLinear: ≤ 8,0x10-6 °C-1; ResistenciaAoChoqueTermico: Resiste; DurabilidadeInterior: Cumpre; DurabilidadeResistenciaAoGeloDegelo: Resiste; ResistenciaAoEscorregamentoDIN51130: R9; ResistenciaAoEscorregamentoDIN51097: A; ResistenciaAoEscorregamentoENV51097: A; ResistenciaAoEscorregamentoENV12633: Class 1; ResistenciaAoEscorregamentoBS7976: -; ResistenciaAoEscorregamentoANSIA1371: ≥0,42; ResistenciaAoDeslizamentoENV12633: Class 1; ResistenciaAoDeslizamentoBS7976: -; ResistenciaAsManchas: Class 5; LibertacaoDeCadmio: 0; LibertacaoDeChumbo: 0
Type - IFC.REVIGRÉS-Dados de especificação-Wall Covering - VariacaoTonalidade: 3; NivelDeTrafego: 5; EPavimento: Sim; ERevestimento: Sim; EExterno: Sim
Type - IFC.REVIGRÉS-Dados geométricos-Wall Covering - AlturaNominal: 8.5 mm; ComprimentoNominal: 16.5 mm; LarguraNominal: 19 mm
Type - IFC.REVIGRÉS-Dados de sustentabilidade-Wall Covering - PotencialPrivacaoDeAguaConsumoDeAguaPonderado: 4.5; EnergiaTermicaExportada: 0; ItemENovo: Sim; ItemEParcialmenteReciclado: 0.23; ItemEReciclado: Sim; VidaÚtilEsperada: 50; SubstanciasPerigosas: Não; PotencialDeEsgotamentoAbioticoDosRecursosNaoFosseisMineraisEMetais: 0.000701; PotencialDeAquecimentoGlobalBiogenico: -0.48; CombustiveisFosseisComPotencialDeAquecimentoGlobal: 13.9; PotencialDeAquecimentoGlobalUsoDoSoloEMudancaDeUsoDoSolo: 0.0246; PotencialDeEutrofizacaoFraccaoDeNutrientesQueAtingemOCompartimentoFinalDeAguaDoce: 0.000189; PotencialDeEutrofizacaoFraccaoDeNutrientesQueAtingemOCompartimentoFinalMarinho: 0.0122; EnergiaRecuperada: 0.00739; ConsumoDeAguaDoce: 0.113; UtilizacaoLiquidaDeAguaDoce: 0.113; ResiduosPerigososEliminados: 0.00221; ResiduosNaoPerigososEliminados: 1.83; MassaTotalDeResiduosRadioactivosEliminados: 0.000394; EnergiaElectricaExportada: 1.55; MateriaisParaRecuperacaoDeEnergia: 0.00739; MateriaisParaReciclagem: 0.0253; UnidadeEPD: 1 m²
Type - IFC.REVIGRÉS-Dados gerais-Wall Covering - Nome: REVIGRÉS-LOCUS-HEXAGONO-16.5x19-SILK-GRIS; TipoProduto: Prensado a seco: grupo BIa UGL | Grés porcelânico técnico; NumeroDeRegistoDAP: EPD-REV-20240006-CCC1-EN; ReferenciaDAP: -; UrlDOP: -
Classification: C3010 (Uniformat)
Pset_WallCommon - ExtendToStructure: no; LoadBearing: no
IFC.REVIGRÉS-Dados do fabricante-Wall Covering - Type: Basic Wall: REVIGRÉS-LOCUS-HEXAGONO-16,5X19-SILK-GRIS
IFC.REVIGRÉS-Dados de desempenho-Wall Covering - Type: Basic Wall: REVIGRÉS-LOCUS-HEXAGONO-16,5X19-SILK-GRIS
IFC.REVIGRÉS-Dados de especificação-Wall Covering - Type: Basic Wall: REVIGRÉS-LOCUS-HEXAGONO-16,5X19-SILK-GRIS
IFC.REVIGRÉS-Dados geométricos-Wall Covering - Type: Basic Wall: REVIGRÉS-LOCUS-HEXAGONO-16,5X19-SILK-GRIS
IFC.REVIGRÉS-Dados de sustentabilidade-Wall Covering - Type: Basic Wall: REVIGRÉS-LOCUS-HEXAGONO-16,5X19-SILK-GRIS

# IfcWallStandardCase: Basic Wall:REVIGRÉS-LOCUS-HEXAGONO-16,5X19-SILK-SMOG, Basic Wall:REVIGRÉS-LOCUS-HEXAGONO-16,5X19-SILK-SMOG:37900
In: Level 1
Type - PredefinedType: STANDARD; Material: REVIGRÉS-LOCUS-HEXAGONO-16,5x19-SILK-SMOG 8.5 mm
Type - Pset_ElementShading - Roughness: 304.8 mm
Type - Pset_ManufacturerTypeInformation - Manufacturer: REVIGRÉS
Type - Pset_ProductRequirements - Category: Walls
Type - Pset_QuantityTakeOff - Reference: 332GV3V791
Type - Pset_ReinforcementBarPitchOfWall - Description: Stone effect in wall and floor full body porcelain tile; Reference: 332GV3V791
Type - Pset_WallCommon - IsExternal: no; Reference: 332GV3V791
Type - IFC.REVIGRÉS-Dados do fabricante-Wall Covering - FabricanteURL: https://www.revigres.pt/; ReferenciaModelo: Locus; NumeroGlobalDeItemComercial: 332GV3V791; Acabamento: SILK; Material: Grés porcelânico; IdentificadorDoOperadorEconomico: 501840856; UrlFabricanteArtigo: https://www.revigres.pt/colecoes/locus; PaisOrigem: Portugal
Type - IFC.REVIGRÉS-Dados de desempenho-Wall Covering - Rectilinearidade: ± 0.2% máx.± 0.8 mm; Ortogonalidade: ± 0.2% máx.± 1.5 mm; PlanaridadeDaSuperficie: ± 0.3% máx. ± 1.8 mm; QualidadeDaSuperficie: Cumpre; AbsorcaoDeAgua: < 0.05%; ModuloDeRuptura: > 45 N/mm²; ResistenciaAFlexao: > 2000 N; ResistenciaAAbrasaoProfunda: < 120 mm³; DilatacaoTermicaLinear: ≤ 8,0x10-6 °C-1; ResistenciaAoChoqueTermico: Resiste; DurabilidadeInterior: Cumpre; DurabilidadeResistenciaAoGeloDegelo: Resiste; ResistenciaAoEscorregamentoDIN51130: R9; ResistenciaAoEscorregamentoDIN51097: A; ResistenciaAoEscorregamentoENV51097: A; ResistenciaAoEscorregamentoENV12633: Class 1; ResistenciaAoEscorregamentoBS7976: -; ResistenciaAoEscorregamentoANSIA1371: ≥0,42; ResistenciaAoDeslizamentoENV12633: Class 1; ResistenciaAoDeslizamentoBS7976: -; ResistenciaAsManchas: Class 5; LibertacaoDeCadmio: 0; LibertacaoDeChumbo: 0
Type - IFC.REVIGRÉS-Dados de especificação-Wall Covering - VariacaoTonalidade: 3; NivelDeTrafego: 5; EPavimento: Sim; ERevestimento: Sim; EExterno: Sim
Type - IFC.REVIGRÉS-Dados geométricos-Wall Covering - AlturaNominal: 8.5 mm; ComprimentoNominal: 16.5 mm; LarguraNominal: 19 mm
Type - IFC.REVIGRÉS-Dados de sustentabilidade-Wall Covering - PotencialPrivacaoDeAguaConsumoDeAguaPonderado: 4.5; EnergiaTermicaExportada: 0; ItemENovo: Sim; ItemEParcialmenteReciclado: 0.29; ItemEReciclado: Sim; VidaÚtilEsperada: 50; SubstanciasPerigosas: Não; PotencialDeEsgotamentoAbioticoDosRecursosNaoFosseisMineraisEMetais: 0.000701; PotencialDeAquecimentoGlobalBiogenico: -0.48; CombustiveisFosseisComPotencialDeAquecimentoGlobal: 13.9; PotencialDeAquecimentoGlobalUsoDoSoloEMudancaDeUsoDoSolo: 0.0246; PotencialDeEutrofizacaoFraccaoDeNutrientesQueAtingemOCompartimentoFinalDeAguaDoce: 0.000189; PotencialDeEutrofizacaoFraccaoDeNutrientesQueAtingemOCompartimentoFinalMarinho: 0.0122; EnergiaRecuperada: 0.00739; ConsumoDeAguaDoce: 0.113; UtilizacaoLiquidaDeAguaDoce: 0.113; ResiduosPerigososEliminados: 0.00221; ResiduosNaoPerigososEliminados: 1.83; MassaTotalDeResiduosRadioactivosEliminados: 0.000394; EnergiaElectricaExportada: 1.55; MateriaisParaRecuperacaoDeEnergia: 0.00739; MateriaisParaReciclagem: 0.0253; UnidadeEPD: 1 m²
Type - IFC.REVIGRÉS-Dados gerais-Wall Covering - Nome: REVIGRÉS-LOCUS-HEXAGONO-16.5x19-SILK-SMOG; TipoProduto: Prensado a seco: grupo BIa UGL | Grés porcelânico técnico; NumeroDeRegistoDAP: EPD-REV-20240006-CCC1-EN; ReferenciaDAP: -; UrlDOP: -
Classification: C3010 (Uniformat)
Pset_WallCommon - ExtendToStructure: no; LoadBearing: no
IFC.REVIGRÉS-Dados do fabricante-Wall Covering - Type: Basic Wall: REVIGRÉS-LOCUS-HEXAGONO-16,5X19-SILK-SMOG
IFC.REVIGRÉS-Dados de desempenho-Wall Covering - Type: Basic Wall: REVIGRÉS-LOCUS-HEXAGONO-16,5X19-SILK-SMOG
IFC.REVIGRÉS-Dados de especificação-Wall Covering - Type: Basic Wall: REVIGRÉS-LOCUS-HEXAGONO-16,5X19-SILK-SMOG
IFC.REVIGRÉS-Dados geométricos-Wall Covering - Type: Basic Wall: REVIGRÉS-LOCUS-HEXAGONO-16,5X19-SILK-SMOG
IFC.REVIGRÉS-Dados de sustentabilidade-Wall Covering - Type: Basic Wall: REVIGRÉS-LOCUS-HEXAGONO-16,5X19-SILK-SMOG

# IfcWallStandardCase: Basic Wall:REVIGRÉS-LOCUS-HEXAGONO-16,5X19-SOFT GRIP-ALLOY, Basic Wall:REVIGRÉS-LOCUS-HEXAGONO-16,5X19-SOFT GRIP-ALLOY:112815
In: Level 1
Type - PredefinedType: STANDARD; Material: REVIGRÉS-LOCUS-HEXAGONO-16,5x19-SOFT GRIP-ALLOY 8.5 mm
Type - Pset_ElementShading - Roughness: 304.8 mm
Type - Pset_ManufacturerTypeInformation - Manufacturer: REVIGRÉS
Type - Pset_ProductRequirements - Category: Walls
Type - Pset_QuantityTakeOff - Reference: 332FV3V761
Type - Pset_ReinforcementBarPitchOfWall - Description: Stone effect in wall and floor full body porcelain tile; Reference: 332FV3V761
Type - Pset_WallCommon - IsExternal: no; Reference: 332FV3V761
Type - IFC.REVIGRÉS-Dados do fabricante-Wall Covering - FabricanteURL: https://www.revigres.pt/; ReferenciaModelo: Locus; NumeroGlobalDeItemComercial: 332FV3V761; Acabamento: SOFT; Material: Grés porcelânico; IdentificadorDoOperadorEconomico: 501840856; UrlFabricanteArtigo: https://www.revigres.pt/colecoes/locus; PaisOrigem: Portugal
Type - IFC.REVIGRÉS-Dados de desempenho-Wall Covering - Rectilinearidade: ± 0.2% máx ± 1.0 mm; Ortogonalidade: ± 0.2% máx.± 1.5 mm; PlanaridadeDaSuperficie: ± 0.3% máx. ± 1.8 mm; QualidadeDaSuperficie: Cumpre; AbsorcaoDeAgua: < 0.05%; ModuloDeRuptura: > 45 N/mm²; ResistenciaAFlexao: > 2000 N; ResistenciaAAbrasaoProfunda: < 120 mm³; DilatacaoTermicaLinear: ≤ 8,0x10-6 °C-1; ResistenciaAoChoqueTermico: Resiste; DurabilidadeInterior: Cumpre; DurabilidadeResistenciaAoGeloDegelo: Resiste; ResistenciaAoEscorregamentoDIN51130: R11; ResistenciaAoEscorregamentoDIN51097: A; ResistenciaAoEscorregamentoENV51097: A; ResistenciaAoEscorregamentoENV12633: Class 2; ResistenciaAoEscorregamentoBS7976: > 36; ResistenciaAoEscorregamentoANSIA1371: ≥0,42; ResistenciaAoDeslizamentoENV12633: Class 2; ResistenciaAoDeslizamentoBS7976: > 36; ResistenciaAsManchas: Class 5; LibertacaoDeCadmio: 0; LibertacaoDeChumbo: 0
Type - IFC.REVIGRÉS-Dados de especificação-Wall Covering - VariacaoTonalidade: 3; NivelDeTrafego: 5; EPavimento: Sim; ERevestimento: Sim; EExterno: Sim
Type - IFC.REVIGRÉS-Dados geométricos-Wall Covering - AlturaNominal: 8.5 mm; ComprimentoNominal: 16.5 mm; LarguraNominal: 19 mm
Type - IFC.REVIGRÉS-Dados de sustentabilidade-Wall Covering - ItemEParcialmenteReciclado: 0; PotencialPrivacaoDeAguaConsumoDeAguaPonderado: 4.5; EnergiaTermicaExportada: 0; ItemENovo: Sim; ItemEReciclado: Não; VidaÚtilEsperada: 50; SubstanciasPerigosas: Não; PotencialDeEsgotamentoAbioticoDosRecursosNaoFosseisMineraisEMetais: 0.000701; PotencialDeAquecimentoGlobalBiogenico: -0.48; CombustiveisFosseisComPotencialDeAquecimentoGlobal: 13.9; PotencialDeAquecimentoGlobalUsoDoSoloEMudancaDeUsoDoSolo: 0.0246; PotencialDeEutrofizacaoFraccaoDeNutrientesQueAtingemOCompartimentoFinalDeAguaDoce: 0.000189; PotencialDeEutrofizacaoFraccaoDeNutrientesQueAtingemOCompartimentoFinalMarinho: 0.0122; EnergiaRecuperada: 0.00739; ConsumoDeAguaDoce: 0.113; UtilizacaoLiquidaDeAguaDoce: 0.113; ResiduosPerigososEliminados: 0.00221; ResiduosNaoPerigososEliminados: 1.83; MassaTotalDeResiduosRadioactivosEliminados: 0.000394; EnergiaElectricaExportada: 1.55; MateriaisParaRecuperacaoDeEnergia: 0.00739; MateriaisParaReciclagem: 0.0253; UnidadeEPD: 1 m²
Type - IFC.REVIGRÉS-Dados gerais-Wall Covering - Nome: REVIGRÉS-LOCUS-HEXAGONO-16.5x19-SOFT GRIP-ALLOY; TipoProduto: Prensado a seco: grupo BIa UGL | Grés porcelânico técnico; NumeroDeRegistoDAP: EPD-REV-20240006-CCC1-EN; ReferenciaDAP: -; UrlDOP: -
Classification: C3010 (Uniformat)
Pset_WallCommon - ExtendToStructure: no; LoadBearing: no
IFC.REVIGRÉS-Dados do fabricante-Wall Covering - Type: Basic Wall: REVIGRÉS-LOCUS-HEXAGONO-16,5X19-SOFT GRIP-ALLOY
IFC.REVIGRÉS-Dados de desempenho-Wall Covering - Type: Basic Wall: REVIGRÉS-LOCUS-HEXAGONO-16,5X19-SOFT GRIP-ALLOY
IFC.REVIGRÉS-Dados de especificação-Wall Covering - Type: Basic Wall: REVIGRÉS-LOCUS-HEXAGONO-16,5X19-SOFT GRIP-ALLOY
IFC.REVIGRÉS-Dados geométricos-Wall Covering - Type: Basic Wall: REVIGRÉS-LOCUS-HEXAGONO-16,5X19-SOFT GRIP-ALLOY
IFC.REVIGRÉS-Dados de sustentabilidade-Wall Covering - Type: Basic Wall: REVIGRÉS-LOCUS-HEXAGONO-16,5X19-SOFT GRIP-ALLOY

# IfcWallStandardCase: Basic Wall:REVIGRÉS-LOCUS-HEXAGONO-16,5X19-SOFT GRIP-BONE, Basic Wall:REVIGRÉS-LOCUS-HEXAGONO-16,5X19-SOFT GRIP-BONE:112823
In: Level 1
Type - PredefinedType: STANDARD; Material: REVIGRÉS-LOCUS-HEXAGONO-16,5x19-SOFT GRIP-BONE 8.5 mm
Type - Pset_ElementShading - Roughness: 304.8 mm
Type - Pset_ManufacturerTypeInformation - Manufacturer: REVIGRÉS
Type - Pset_ProductRequirements - Category: Walls
Type - Pset_QuantityTakeOff - Reference: 332FV3V771
Type - Pset_ReinforcementBarPitchOfWall - Description: Stone effect in wall and floor full body porcelain tile; Reference: 332FV3V771
Type - Pset_WallCommon - IsExternal: no; Reference: 332FV3V771
Type - IFC.REVIGRÉS-Dados do fabricante-Wall Covering - FabricanteURL: https://www.revigres.pt/; ReferenciaModelo: Locus; NumeroGlobalDeItemComercial: 332FV3V771; Acabamento: SOFT; Material: Grés porcelânico; IdentificadorDoOperadorEconomico: 501840856; UrlFabricanteArtigo: https://www.revigres.pt/colecoes/locus; PaisOrigem: Portugal
Type - IFC.REVIGRÉS-Dados de desempenho-Wall Covering - Rectilinearidade: ± 0.2% máx ± 1.0 mm; Ortogonalidade: ± 0.2% máx.± 1.5 mm; PlanaridadeDaSuperficie: ± 0.3% máx. ± 1.8 mm; QualidadeDaSuperficie: Cumpre; AbsorcaoDeAgua: < 0.05%; ModuloDeRuptura: > 45 N/mm²; ResistenciaAFlexao: > 2000 N; ResistenciaAAbrasaoProfunda: < 120 mm³; DilatacaoTermicaLinear: ≤ 8,0x10-6 °C-1; ResistenciaAoChoqueTermico: Resiste; DurabilidadeInterior: Cumpre; DurabilidadeResistenciaAoGeloDegelo: Resiste; ResistenciaAoEscorregamentoDIN51130: R11; ResistenciaAoEscorregamentoDIN51097: A; ResistenciaAoEscorregamentoENV51097: A; ResistenciaAoEscorregamentoENV12633: Class 2; ResistenciaAoEscorregamentoBS7976: > 36; ResistenciaAoEscorregamentoANSIA1371: ≥0,42; ResistenciaAoDeslizamentoENV12633: Class 2; ResistenciaAoDeslizamentoBS7976: > 36; ResistenciaAsManchas: Class 5; LibertacaoDeCadmio: 0; LibertacaoDeChumbo: 0
Type - IFC.REVIGRÉS-Dados de especificação-Wall Covering - VariacaoTonalidade: 3; NivelDeTrafego: 5; EPavimento: Sim; ERevestimento: Sim; EExterno: Sim
Type - IFC.REVIGRÉS-Dados geométricos-Wall Covering - AlturaNominal: 8.5 mm; ComprimentoNominal: 16.5 mm; LarguraNominal: 19 mm
Type - IFC.REVIGRÉS-Dados de sustentabilidade-Wall Covering - ItemEParcialmenteReciclado: 0; PotencialPrivacaoDeAguaConsumoDeAguaPonderado: 4.5; EnergiaTermicaExportada: 0; ItemENovo: Sim; ItemEReciclado: Não; VidaÚtilEsperada: 50; SubstanciasPerigosas: Não; PotencialDeEsgotamentoAbioticoDosRecursosNaoFosseisMineraisEMetais: 0.000701; PotencialDeAquecimentoGlobalBiogenico: -0.48; CombustiveisFosseisComPotencialDeAquecimentoGlobal: 13.9; PotencialDeAquecimentoGlobalUsoDoSoloEMudancaDeUsoDoSolo: 0.0246; PotencialDeEutrofizacaoFraccaoDeNutrientesQueAtingemOCompartimentoFinalDeAguaDoce: 0.000189; PotencialDeEutrofizacaoFraccaoDeNutrientesQueAtingemOCompartimentoFinalMarinho: 0.0122; EnergiaRecuperada: 0.00739; ConsumoDeAguaDoce: 0.113; UtilizacaoLiquidaDeAguaDoce: 0.113; ResiduosPerigososEliminados: 0.00221; ResiduosNaoPerigososEliminados: 1.83; MassaTotalDeResiduosRadioactivosEliminados: 0.000394; EnergiaElectricaExportada: 1.55; MateriaisParaRecuperacaoDeEnergia: 0.00739; MateriaisParaReciclagem: 0.0253; UnidadeEPD: 1 m²
Type - IFC.REVIGRÉS-Dados gerais-Wall Covering - Nome: REVIGRÉS-LOCUS-HEXAGONO-16.5x19-SOFT GRIP-BONE; TipoProduto: Prensado a seco: grupo BIa UGL | Grés porcelânico técnico; NumeroDeRegistoDAP: EPD-REV-20240006-CCC1-EN; ReferenciaDAP: -; UrlDOP: -
Classification: C3010 (Uniformat)
Pset_WallCommon - ExtendToStructure: no; LoadBearing: no
IFC.REVIGRÉS-Dados do fabricante-Wall Covering - Type: Basic Wall: REVIGRÉS-LOCUS-HEXAGONO-16,5X19-SOFT GRIP-BONE
IFC.REVIGRÉS-Dados de desempenho-Wall Covering - Type: Basic Wall: REVIGRÉS-LOCUS-HEXAGONO-16,5X19-SOFT GRIP-BONE
IFC.REVIGRÉS-Dados de especificação-Wall Covering - Type: Basic Wall: REVIGRÉS-LOCUS-HEXAGONO-16,5X19-SOFT GRIP-BONE
IFC.REVIGRÉS-Dados geométricos-Wall Covering - Type: Basic Wall: REVIGRÉS-LOCUS-HEXAGONO-16,5X19-SOFT GRIP-BONE
IFC.REVIGRÉS-Dados de sustentabilidade-Wall Covering - Type: Basic Wall: REVIGRÉS-LOCUS-HEXAGONO-16,5X19-SOFT GRIP-BONE

# IfcWallStandardCase: Basic Wall:REVIGRÉS-LOCUS-HEXAGONO-16,5X19-SOFT GRIP-GRIS, Basic Wall:REVIGRÉS-LOCUS-HEXAGONO-16,5X19-SOFT GRIP-GRIS:112831
In: Level 1
Type - PredefinedType: STANDARD; Material: REVIGRÉS-LOCUS-HEXAGONO-16,5x19-SOFT GRIP-GRIS 8.5 mm
Type - Pset_ElementShading - Roughness: 304.8 mm
Type - Pset_ManufacturerTypeInformation - Manufacturer: REVIGRÉS
Type - Pset_ProductRequirements - Category: Walls
Type - Pset_QuantityTakeOff - Reference: 332FV3V781
Type - Pset_ReinforcementBarPitchOfWall - Description: Stone effect in wall and floor full body porcelain tile; Reference: 332FV3V781
Type - Pset_WallCommon - IsExternal: no; Reference: 332FV3V781
Type - IFC.REVIGRÉS-Dados do fabricante-Wall Covering - FabricanteURL: https://www.revigres.pt/; ReferenciaModelo: Locus; NumeroGlobalDeItemComercial: 332FV3V781; Acabamento: SOFT; Material: Grés porcelânico; IdentificadorDoOperadorEconomico: 501840856; UrlFabricanteArtigo: https://www.revigres.pt/colecoes/locus; PaisOrigem: Portugal
Type - IFC.REVIGRÉS-Dados de desempenho-Wall Covering - Rectilinearidade: ± 0.2% máx ± 1.0 mm; Ortogonalidade: ± 0.2% máx.± 1.5 mm; PlanaridadeDaSuperficie: ± 0.3% máx. ± 1.8 mm; QualidadeDaSuperficie: Cumpre; AbsorcaoDeAgua: < 0.05%; ModuloDeRuptura: > 45 N/mm²; ResistenciaAFlexao: > 2000 N; ResistenciaAAbrasaoProfunda: < 120 mm³; DilatacaoTermicaLinear: ≤ 8,0x10-6 °C-1; ResistenciaAoChoqueTermico: Resiste; DurabilidadeInterior: Cumpre; DurabilidadeResistenciaAoGeloDegelo: Resiste; ResistenciaAoEscorregamentoDIN51130: R11; ResistenciaAoEscorregamentoDIN51097: A; ResistenciaAoEscorregamentoENV51097: A; ResistenciaAoEscorregamentoENV12633: Class 2; ResistenciaAoEscorregamentoBS7976: > 36; ResistenciaAoEscorregamentoANSIA1371: ≥0,42; ResistenciaAoDeslizamentoENV12633: Class 2; ResistenciaAoDeslizamentoBS7976: > 36; ResistenciaAsManchas: Class 5; LibertacaoDeCadmio: 0; LibertacaoDeChumbo: 0
Type - IFC.REVIGRÉS-Dados de especificação-Wall Covering - VariacaoTonalidade: 3; NivelDeTrafego: 5; EPavimento: Sim; ERevestimento: Sim; EExterno: Sim
Type - IFC.REVIGRÉS-Dados geométricos-Wall Covering - AlturaNominal: 8.5 mm; ComprimentoNominal: 16.5 mm; LarguraNominal: 19 mm
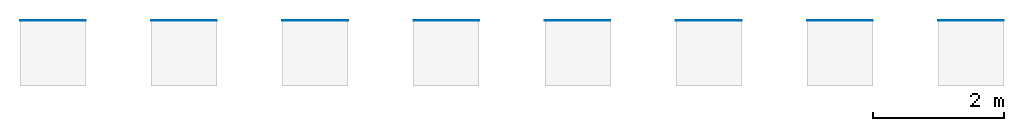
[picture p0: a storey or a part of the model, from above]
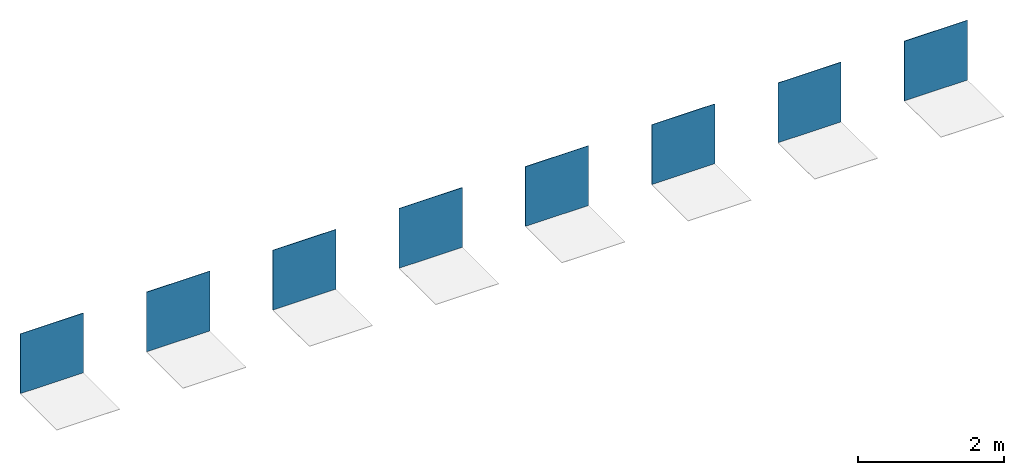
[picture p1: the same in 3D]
Properties of the parts of a building model (IFC2X3), part 2 of 2

# IfcWallStandardCase: Basic Wall:REVIGRÉS-LOCUS-HEXAGONO-16,5X19-SOFT GRIP-GRIS, Basic Wall:REVIGRÉS-LOCUS-HEXAGONO-16,5X19-SOFT GRIP-GRIS:112831
Type - IFC.REVIGRÉS-Dados de sustentabilidade-Wall Covering - PotencialPrivacaoDeAguaConsumoDeAguaPonderado: 4.5; EnergiaTermicaExportada: 0; ItemENovo: Sim; ItemEParcialmenteReciclado: 0.23; ItemEReciclado: Sim; VidaÚtilEsperada: 50; SubstanciasPerigosas: Não; PotencialDeEsgotamentoAbioticoDosRecursosNaoFosseisMineraisEMetais: 0.000701; PotencialDeAquecimentoGlobalBiogenico: -0.48; CombustiveisFosseisComPotencialDeAquecimentoGlobal: 13.9; PotencialDeAquecimentoGlobalUsoDoSoloEMudancaDeUsoDoSolo: 0.0246; PotencialDeEutrofizacaoFraccaoDeNutrientesQueAtingemOCompartimentoFinalDeAguaDoce: 0.000189; PotencialDeEutrofizacaoFraccaoDeNutrientesQueAtingemOCompartimentoFinalMarinho: 0.0122; EnergiaRecuperada: 0.00739; ConsumoDeAguaDoce: 0.113; UtilizacaoLiquidaDeAguaDoce: 0.113; ResiduosPerigososEliminados: 0.00221; ResiduosNaoPerigososEliminados: 1.83; MassaTotalDeResiduosRadioactivosEliminados: 0.000394; EnergiaElectricaExportada: 1.55; MateriaisParaRecuperacaoDeEnergia: 0.00739; MateriaisParaReciclagem: 0.0253; UnidadeEPD: 1 m²
Type - IFC.REVIGRÉS-Dados gerais-Wall Covering - Nome: REVIGRÉS-LOCUS-HEXAGONO-16.5x19-SOFT GRIP-GRIS; TipoProduto: Prensado a seco: grupo BIa UGL | Grés porcelânico técnico; NumeroDeRegistoDAP: EPD-REV-20240006-CCC1-EN; ReferenciaDAP: -; UrlDOP: -
Classification: C3010 (Uniformat)
Pset_WallCommon - ExtendToStructure: no; LoadBearing: no
IFC.REVIGRÉS-Dados do fabricante-Wall Covering - Type: Basic Wall: REVIGRÉS-LOCUS-HEXAGONO-16,5X19-SOFT GRIP-GRIS
IFC.REVIGRÉS-Dados de desempenho-Wall Covering - Type: Basic Wall: REVIGRÉS-LOCUS-HEXAGONO-16,5X19-SOFT GRIP-GRIS
IFC.REVIGRÉS-Dados de especificação-Wall Covering - Type: Basic Wall: REVIGRÉS-LOCUS-HEXAGONO-16,5X19-SOFT GRIP-GRIS
IFC.REVIGRÉS-Dados geométricos-Wall Covering - Type: Basic Wall: REVIGRÉS-LOCUS-HEXAGONO-16,5X19-SOFT GRIP-GRIS
IFC.REVIGRÉS-Dados de sustentabilidade-Wall Covering - Type: Basic Wall: REVIGRÉS-LOCUS-HEXAGONO-16,5X19-SOFT GRIP-GRIS

# IfcWallStandardCase: Basic Wall:REVIGRÉS-LOCUS-HEXAGONO-16,5X19-SOFT GRIP-SMOG, Basic Wall:REVIGRÉS-LOCUS-HEXAGONO-16,5X19-SOFT GRIP-SMOG:112839
In: Level 1
Type - PredefinedType: STANDARD; Material: REVIGRÉS-LOCUS-HEXAGONO-16,5x19-SOFT GRIP-SMOG 8.5 mm
Type - Pset_ElementShading - Roughness: 304.8 mm
Type - Pset_ManufacturerTypeInformation - Manufacturer: REVIGRÉS
Type - Pset_ProductRequirements - Category: Walls
Type - Pset_QuantityTakeOff - Reference: 332FV3V791
Type - Pset_ReinforcementBarPitchOfWall - Description: Stone effect in wall and floor full body porcelain tile; Reference: 332FV3V791
Type - Pset_WallCommon - IsExternal: no; Reference: 332FV3V791
Type - IFC.REVIGRÉS-Dados do fabricante-Wall Covering - FabricanteURL: https://www.revigres.pt/; ReferenciaModelo: Locus; NumeroGlobalDeItemComercial: 332FV3V791; Acabamento: SOFT; Material: Grés porcelânico; IdentificadorDoOperadorEconomico: 501840856; UrlFabricanteArtigo: https://www.revigres.pt/colecoes/locus; PaisOrigem: Portugal
Type - IFC.REVIGRÉS-Dados de desempenho-Wall Covering - Rectilinearidade: ± 0.2% máx ± 1.0 mm; Ortogonalidade: ± 0.2% máx.± 1.5 mm; PlanaridadeDaSuperficie: ± 0.3% máx. ± 1.8 mm; QualidadeDaSuperficie: Cumpre; AbsorcaoDeAgua: < 0.05%; ModuloDeRuptura: > 45 N/mm²; ResistenciaAFlexao: > 2000 N; ResistenciaAAbrasaoProfunda: < 120 mm³; DilatacaoTermicaLinear: ≤ 8,0x10-6 °C-1; ResistenciaAoChoqueTermico: Resiste; DurabilidadeInterior: Cumpre; DurabilidadeResistenciaAoGeloDegelo: Resiste; ResistenciaAoEscorregamentoDIN51130: R11; ResistenciaAoEscorregamentoDIN51097: A; ResistenciaAoEscorregamentoENV51097: A; ResistenciaAoEscorregamentoENV12633: Class 2; ResistenciaAoEscorregamentoBS7976: > 36; ResistenciaAoEscorregamentoANSIA1371: ≥0,42; ResistenciaAoDeslizamentoENV12633: Class 2; ResistenciaAoDeslizamentoBS7976: > 36; ResistenciaAsManchas: Class 5; LibertacaoDeCadmio: 0; LibertacaoDeChumbo: 0
Type - IFC.REVIGRÉS-Dados de especificação-Wall Covering - VariacaoTonalidade: 3; NivelDeTrafego: 5; EPavimento: Sim; ERevestimento: Sim; EExterno: Sim
Type - IFC.REVIGRÉS-Dados geométricos-Wall Covering - AlturaNominal: 8.5 mm; ComprimentoNominal: 16.5 mm; LarguraNominal: 19 mm
Type - IFC.REVIGRÉS-Dados de sustentabilidade-Wall Covering - PotencialPrivacaoDeAguaConsumoDeAguaPonderado: 4.5; EnergiaTermicaExportada: 0; ItemENovo: Sim; ItemEParcialmenteReciclado: 0.29; ItemEReciclado: Sim; VidaÚtilEsperada: 50; SubstanciasPerigosas: Não; PotencialDeEsgotamentoAbioticoDosRecursosNaoFosseisMineraisEMetais: 0.000701; PotencialDeAquecimentoGlobalBiogenico: -0.48; CombustiveisFosseisComPotencialDeAquecimentoGlobal: 13.9; PotencialDeAquecimentoGlobalUsoDoSoloEMudancaDeUsoDoSolo: 0.0246; PotencialDeEutrofizacaoFraccaoDeNutrientesQueAtingemOCompartimentoFinalDeAguaDoce: 0.000189; PotencialDeEutrofizacaoFraccaoDeNutrientesQueAtingemOCompartimentoFinalMarinho: 0.0122; EnergiaRecuperada: 0.00739; ConsumoDeAguaDoce: 0.113; UtilizacaoLiquidaDeAguaDoce: 0.113; ResiduosPerigososEliminados: 0.00221; ResiduosNaoPerigososEliminados: 1.83; MassaTotalDeResiduosRadioactivosEliminados: 0.000394; EnergiaElectricaExportada: 1.55; MateriaisParaRecuperacaoDeEnergia: 0.00739; MateriaisParaReciclagem: 0.0253; UnidadeEPD: 1 m²
Type - IFC.REVIGRÉS-Dados gerais-Wall Covering - Nome: REVIGRÉS-LOCUS-HEXAGONO-16.5x19-SOFT GRIP-SMOG; TipoProduto: Prensado a seco: grupo BIa UGL | Grés porcelânico técnico; NumeroDeRegistoDAP: EPD-REV-20240006-CCC1-EN; ReferenciaDAP: -; UrlDOP: -
Classification: C3010 (Uniformat)
Pset_WallCommon - ExtendToStructure: no; LoadBearing: no
IFC.REVIGRÉS-Dados do fabricante-Wall Covering - Type: Basic Wall: REVIGRÉS-LOCUS-HEXAGONO-16,5X19-SOFT GRIP-SMOG
IFC.REVIGRÉS-Dados de desempenho-Wall Covering - Type: Basic Wall: REVIGRÉS-LOCUS-HEXAGONO-16,5X19-SOFT GRIP-SMOG
IFC.REVIGRÉS-Dados de especificação-Wall Covering - Type: Basic Wall: REVIGRÉS-LOCUS-HEXAGONO-16,5X19-SOFT GRIP-SMOG
IFC.REVIGRÉS-Dados geométricos-Wall Covering - Type: Basic Wall: REVIGRÉS-LOCUS-HEXAGONO-16,5X19-SOFT GRIP-SMOG
IFC.REVIGRÉS-Dados de sustentabilidade-Wall Covering - Type: Basic Wall: REVIGRÉS-LOCUS-HEXAGONO-16,5X19-SOFT GRIP-SMOG
